# Generated deterministically by seda-macro-lef-normalizer-v1; recipe orfs-ng45-fakeram-metal3-coupledl2-pg-v1.
VERSION 5.8 ;
BUSBITCHARS "[]" ;
DIVIDERCHAR "/" ;

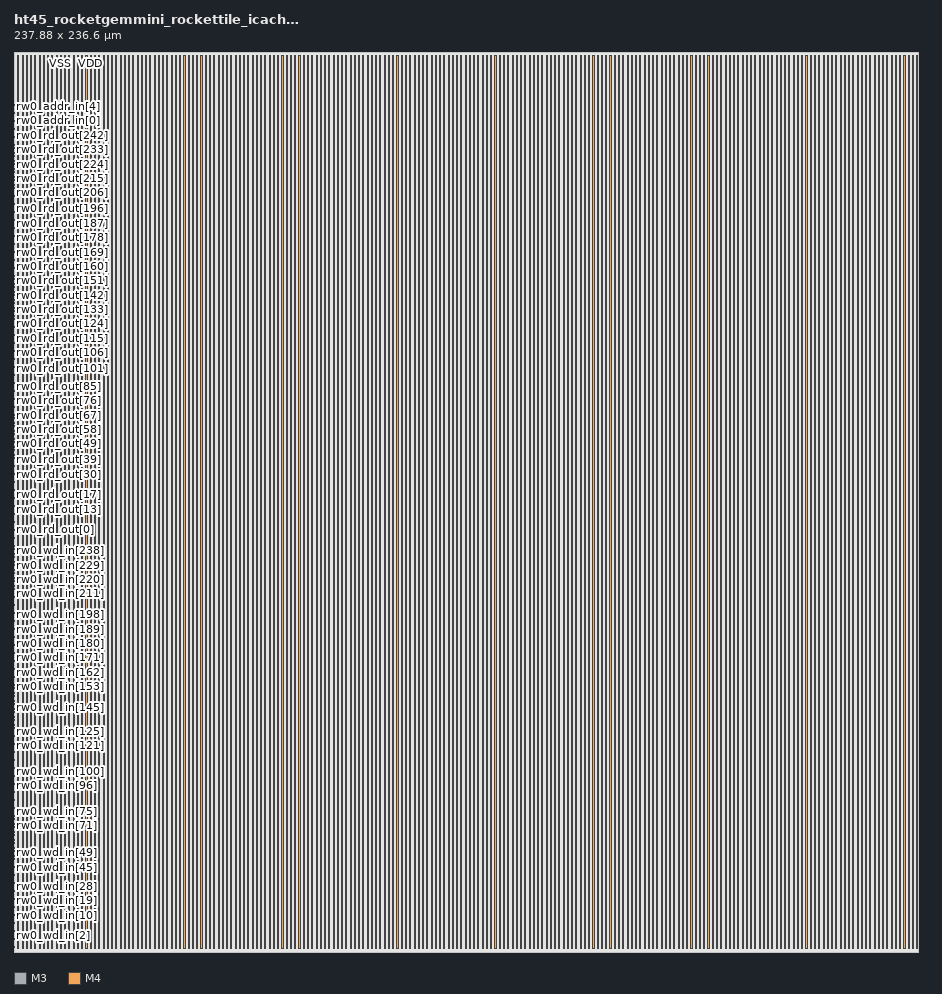
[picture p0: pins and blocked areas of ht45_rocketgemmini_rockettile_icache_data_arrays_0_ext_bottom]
MACRO ht45_rocketgemmini_rockettile_icache_data_arrays_0_ext_bottom
  FOREIGN ht45_rocketgemmini_rockettile_icache_data_arrays_0_ext_bottom 0 0 ;
  CLASS COVER ;
  ORIGIN 0 0 ;
  SIZE 237.88 BY 236.6 ;
  SYMMETRY X Y R90 ;
  PIN rw0_wmask_in[0]
    DIRECTION INPUT ;
    USE SIGNAL ;
    SHAPE ABUTMENT ;
    PORT
      LAYER M3 ;
      RECT 0 0.035 0.07 0.105 ;
    END
  END rw0_wmask_in[0]
  PIN rw0_wmask_in[1]
    DIRECTION INPUT ;
    USE SIGNAL ;
    SHAPE ABUTMENT ;
    PORT
      LAYER M3 ;
      RECT 0 0.455 0.07 0.525 ;
    END
  END rw0_wmask_in[1]
  PIN rw0_wmask_in[2]
    DIRECTION INPUT ;
    USE SIGNAL ;
    SHAPE ABUTMENT ;
    PORT
      LAYER M3 ;
      RECT 0 0.875 0.07 0.945 ;
    END
  END rw0_wmask_in[2]
  PIN rw0_wmask_in[3]
    DIRECTION INPUT ;
    USE SIGNAL ;
    SHAPE ABUTMENT ;
    PORT
      LAYER M3 ;
      RECT 0 1.295 0.07 1.365 ;
    END
  END rw0_wmask_in[3]
  PIN rw0_wmask_in[4]
    DIRECTION INPUT ;
    USE SIGNAL ;
    SHAPE ABUTMENT ;
    PORT
      LAYER M3 ;
      RECT 0 1.715 0.07 1.785 ;
    END
  END rw0_wmask_in[4]
  PIN rw0_wmask_in[5]
    DIRECTION INPUT ;
    USE SIGNAL ;
    SHAPE ABUTMENT ;
    PORT
      LAYER M3 ;
      RECT 0 2.135 0.07 2.205 ;
    END
  END rw0_wmask_in[5]
  PIN rw0_wmask_in[6]
    DIRECTION INPUT ;
    USE SIGNAL ;
    SHAPE ABUTMENT ;
    PORT
      LAYER M3 ;
      RECT 0 2.555 0.07 2.625 ;
    END
  END rw0_wmask_in[6]
  PIN rw0_wmask_in[7]
    DIRECTION INPUT ;
    USE SIGNAL ;
    SHAPE ABUTMENT ;
    PORT
      LAYER M3 ;
      RECT 0 2.975 0.07 3.045 ;
    END
  END rw0_wmask_in[7]
  PIN rw0_wd_in[0]
    DIRECTION INPUT ;
    USE SIGNAL ;
    SHAPE ABUTMENT ;
    PORT
      LAYER M3 ;
      RECT 0 3.395 0.07 3.465 ;
    END
  END rw0_wd_in[0]
  PIN rw0_wd_in[1]
    DIRECTION INPUT ;
    USE SIGNAL ;
    SHAPE ABUTMENT ;
    PORT
      LAYER M3 ;
      RECT 0 3.815 0.07 3.885 ;
    END
  END rw0_wd_in[1]
  PIN rw0_wd_in[2]
    DIRECTION INPUT ;
    USE SIGNAL ;
    SHAPE ABUTMENT ;
    PORT
      LAYER M3 ;
      RECT 0 4.235 0.07 4.305 ;
    END
  END rw0_wd_in[2]
  PIN rw0_wd_in[3]
    DIRECTION INPUT ;
    USE SIGNAL ;
    SHAPE ABUTMENT ;
    PORT
      LAYER M3 ;
      RECT 0 4.655 0.07 4.725 ;
    END
  END rw0_wd_in[3]
  PIN rw0_wd_in[4]
    DIRECTION INPUT ;
    USE SIGNAL ;
    SHAPE ABUTMENT ;
    PORT
      LAYER M3 ;
      RECT 0 5.075 0.07 5.145 ;
    END
  END rw0_wd_in[4]
  PIN rw0_wd_in[5]
    DIRECTION INPUT ;
    USE SIGNAL ;
    SHAPE ABUTMENT ;
    PORT
      LAYER M3 ;
      RECT 0 5.495 0.07 5.565 ;
    END
  END rw0_wd_in[5]
  PIN rw0_wd_in[6]
    DIRECTION INPUT ;
    USE SIGNAL ;
    SHAPE ABUTMENT ;
    PORT
      LAYER M3 ;
      RECT 0 5.915 0.07 5.985 ;
    END
  END rw0_wd_in[6]
  PIN rw0_wd_in[7]
    DIRECTION INPUT ;
    USE SIGNAL ;
    SHAPE ABUTMENT ;
    PORT
      LAYER M3 ;
      RECT 0 6.335 0.07 6.405 ;
    END
  END rw0_wd_in[7]
  PIN rw0_wd_in[8]
    DIRECTION INPUT ;
    USE SIGNAL ;
    SHAPE ABUTMENT ;
    PORT
      LAYER M3 ;
      RECT 0 6.755 0.07 6.825 ;
    END
  END rw0_wd_in[8]
  PIN rw0_wd_in[9]
    DIRECTION INPUT ;
    USE SIGNAL ;
    SHAPE ABUTMENT ;
    PORT
      LAYER M3 ;
      RECT 0 7.175 0.07 7.245 ;
    END
  END rw0_wd_in[9]
  PIN rw0_wd_in[10]
    DIRECTION INPUT ;
    USE SIGNAL ;
    SHAPE ABUTMENT ;
    PORT
      LAYER M3 ;
      RECT 0 7.595 0.07 7.665 ;
    END
  END rw0_wd_in[10]
  PIN rw0_wd_in[11]
    DIRECTION INPUT ;
    USE SIGNAL ;
    SHAPE ABUTMENT ;
    PORT
      LAYER M3 ;
      RECT 0 8.015 0.07 8.085 ;
    END
  END rw0_wd_in[11]
  PIN rw0_wd_in[12]
    DIRECTION INPUT ;
    USE SIGNAL ;
    SHAPE ABUTMENT ;
    PORT
      LAYER M3 ;
      RECT 0 8.435 0.07 8.505 ;
    END
  END rw0_wd_in[12]
  PIN rw0_wd_in[13]
    DIRECTION INPUT ;
    USE SIGNAL ;
    SHAPE ABUTMENT ;
    PORT
      LAYER M3 ;
      RECT 0 8.855 0.07 8.925 ;
    END
  END rw0_wd_in[13]
  PIN rw0_wd_in[14]
    DIRECTION INPUT ;
    USE SIGNAL ;
    SHAPE ABUTMENT ;
    PORT
      LAYER M3 ;
      RECT 0 9.275 0.07 9.345 ;
    END
  END rw0_wd_in[14]
  PIN rw0_wd_in[15]
    DIRECTION INPUT ;
    USE SIGNAL ;
    SHAPE ABUTMENT ;
    PORT
      LAYER M3 ;
      RECT 0 9.695 0.07 9.765 ;
    END
  END rw0_wd_in[15]
  PIN rw0_wd_in[16]
    DIRECTION INPUT ;
    USE SIGNAL ;
    SHAPE ABUTMENT ;
    PORT
      LAYER M3 ;
      RECT 0 10.115 0.07 10.185 ;
    END
  END rw0_wd_in[16]
  PIN rw0_wd_in[17]
    DIRECTION INPUT ;
    USE SIGNAL ;
    SHAPE ABUTMENT ;
    PORT
      LAYER M3 ;
      RECT 0 10.535 0.07 10.605 ;
    END
  END rw0_wd_in[17]
  PIN rw0_wd_in[18]
    DIRECTION INPUT ;
    USE SIGNAL ;
    SHAPE ABUTMENT ;
    PORT
      LAYER M3 ;
      RECT 0 10.955 0.07 11.025 ;
    END
  END rw0_wd_in[18]
  PIN rw0_wd_in[19]
    DIRECTION INPUT ;
    USE SIGNAL ;
    SHAPE ABUTMENT ;
    PORT
      LAYER M3 ;
      RECT 0 11.375 0.07 11.445 ;
    END
  END rw0_wd_in[19]
  PIN rw0_wd_in[20]
    DIRECTION INPUT ;
    USE SIGNAL ;
    SHAPE ABUTMENT ;
    PORT
      LAYER M3 ;
      RECT 0 11.795 0.07 11.865 ;
    END
  END rw0_wd_in[20]
  PIN rw0_wd_in[21]
    DIRECTION INPUT ;
    USE SIGNAL ;
    SHAPE ABUTMENT ;
    PORT
      LAYER M3 ;
      RECT 0 12.215 0.07 12.285 ;
    END
  END rw0_wd_in[21]
  PIN rw0_wd_in[22]
    DIRECTION INPUT ;
    USE SIGNAL ;
    SHAPE ABUTMENT ;
    PORT
      LAYER M3 ;
      RECT 0 12.635 0.07 12.705 ;
    END
  END rw0_wd_in[22]
  PIN rw0_wd_in[23]
    DIRECTION INPUT ;
    USE SIGNAL ;
    SHAPE ABUTMENT ;
    PORT
      LAYER M3 ;
      RECT 0 13.055 0.07 13.125 ;
    END
  END rw0_wd_in[23]
  PIN rw0_wd_in[24]
    DIRECTION INPUT ;
    USE SIGNAL ;
    SHAPE ABUTMENT ;
    PORT
      LAYER M3 ;
      RECT 0 13.475 0.07 13.545 ;
    END
  END rw0_wd_in[24]
  PIN rw0_wd_in[25]
    DIRECTION INPUT ;
    USE SIGNAL ;
    SHAPE ABUTMENT ;
    PORT
      LAYER M3 ;
      RECT 0 13.895 0.07 13.965 ;
    END
  END rw0_wd_in[25]
  PIN rw0_wd_in[26]
    DIRECTION INPUT ;
    USE SIGNAL ;
    SHAPE ABUTMENT ;
    PORT
      LAYER M3 ;
      RECT 0 14.315 0.07 14.385 ;
    END
  END rw0_wd_in[26]
  PIN rw0_wd_in[27]
    DIRECTION INPUT ;
    USE SIGNAL ;
    SHAPE ABUTMENT ;
    PORT
      LAYER M3 ;
      RECT 0 14.735 0.07 14.805 ;
    END
  END rw0_wd_in[27]
  PIN rw0_wd_in[28]
    DIRECTION INPUT ;
    USE SIGNAL ;
    SHAPE ABUTMENT ;
    PORT
      LAYER M3 ;
      RECT 0 15.155 0.07 15.225 ;
    END
  END rw0_wd_in[28]
  PIN rw0_wd_in[29]
    DIRECTION INPUT ;
    USE SIGNAL ;
    SHAPE ABUTMENT ;
    PORT
      LAYER M3 ;
      RECT 0 15.575 0.07 15.645 ;
    END
  END rw0_wd_in[29]
  PIN rw0_wd_in[30]
    DIRECTION INPUT ;
    USE SIGNAL ;
    SHAPE ABUTMENT ;
    PORT
      LAYER M3 ;
      RECT 0 15.995 0.07 16.065 ;
    END
  END rw0_wd_in[30]
  PIN rw0_wd_in[31]
    DIRECTION INPUT ;
    USE SIGNAL ;
    SHAPE ABUTMENT ;
    PORT
      LAYER M3 ;
      RECT 0 16.415 0.07 16.485 ;
    END
  END rw0_wd_in[31]
  PIN rw0_wd_in[32]
    DIRECTION INPUT ;
    USE SIGNAL ;
    SHAPE ABUTMENT ;
    PORT
      LAYER M3 ;
      RECT 0 16.835 0.07 16.905 ;
    END
  END rw0_wd_in[32]
  PIN rw0_wd_in[33]
    DIRECTION INPUT ;
    USE SIGNAL ;
    SHAPE ABUTMENT ;
    PORT
      LAYER M3 ;
      RECT 0 17.255 0.07 17.325 ;
    END
  END rw0_wd_in[33]
  PIN rw0_wd_in[34]
    DIRECTION INPUT ;
    USE SIGNAL ;
    SHAPE ABUTMENT ;
    PORT
      LAYER M3 ;
      RECT 0 17.675 0.07 17.745 ;
    END
  END rw0_wd_in[34]
  PIN rw0_wd_in[35]
    DIRECTION INPUT ;
    USE SIGNAL ;
    SHAPE ABUTMENT ;
    PORT
      LAYER M3 ;
      RECT 0 18.095 0.07 18.165 ;
    END
  END rw0_wd_in[35]
  PIN rw0_wd_in[36]
    DIRECTION INPUT ;
    USE SIGNAL ;
    SHAPE ABUTMENT ;
    PORT
      LAYER M3 ;
      RECT 0 18.515 0.07 18.585 ;
    END
  END rw0_wd_in[36]
  PIN rw0_wd_in[37]
    DIRECTION INPUT ;
    USE SIGNAL ;
    SHAPE ABUTMENT ;
    PORT
      LAYER M3 ;
      RECT 0 18.935 0.07 19.005 ;
    END
  END rw0_wd_in[37]
  PIN rw0_wd_in[38]
    DIRECTION INPUT ;
    USE SIGNAL ;
    SHAPE ABUTMENT ;
    PORT
      LAYER M3 ;
      RECT 0 19.355 0.07 19.425 ;
    END
  END rw0_wd_in[38]
  PIN rw0_wd_in[39]
    DIRECTION INPUT ;
    USE SIGNAL ;
    SHAPE ABUTMENT ;
    PORT
      LAYER M3 ;
      RECT 0 19.775 0.07 19.845 ;
    END
  END rw0_wd_in[39]
  PIN rw0_wd_in[40]
    DIRECTION INPUT ;
    USE SIGNAL ;
    SHAPE ABUTMENT ;
    PORT
      LAYER M3 ;
      RECT 0 20.195 0.07 20.265 ;
    END
  END rw0_wd_in[40]
  PIN rw0_wd_in[41]
    DIRECTION INPUT ;
    USE SIGNAL ;
    SHAPE ABUTMENT ;
    PORT
      LAYER M3 ;
      RECT 0 20.615 0.07 20.685 ;
    END
  END rw0_wd_in[41]
  PIN rw0_wd_in[42]
    DIRECTION INPUT ;
    USE SIGNAL ;
    SHAPE ABUTMENT ;
    PORT
      LAYER M3 ;
      RECT 0 21.035 0.07 21.105 ;
    END
  END rw0_wd_in[42]
  PIN rw0_wd_in[43]
    DIRECTION INPUT ;
    USE SIGNAL ;
    SHAPE ABUTMENT ;
    PORT
      LAYER M3 ;
      RECT 0 21.455 0.07 21.525 ;
    END
  END rw0_wd_in[43]
  PIN rw0_wd_in[44]
    DIRECTION INPUT ;
    USE SIGNAL ;
    SHAPE ABUTMENT ;
    PORT
      LAYER M3 ;
      RECT 0 21.875 0.07 21.945 ;
    END
  END rw0_wd_in[44]
  PIN rw0_wd_in[45]
    DIRECTION INPUT ;
    USE SIGNAL ;
    SHAPE ABUTMENT ;
    PORT
      LAYER M3 ;
      RECT 0 22.295 0.07 22.365 ;
    END
  END rw0_wd_in[45]
  PIN rw0_wd_in[46]
    DIRECTION INPUT ;
    USE SIGNAL ;
    SHAPE ABUTMENT ;
    PORT
      LAYER M3 ;
      RECT 0 22.715 0.07 22.785 ;
    END
  END rw0_wd_in[46]
  PIN rw0_wd_in[47]
    DIRECTION INPUT ;
    USE SIGNAL ;
    SHAPE ABUTMENT ;
    PORT
      LAYER M3 ;
      RECT 0 23.135 0.07 23.205 ;
    END
  END rw0_wd_in[47]
  PIN rw0_wd_in[48]
    DIRECTION INPUT ;
    USE SIGNAL ;
    SHAPE ABUTMENT ;
    PORT
      LAYER M3 ;
      RECT 0 23.555 0.07 23.625 ;
    END
  END rw0_wd_in[48]
  PIN rw0_wd_in[49]
    DIRECTION INPUT ;
    USE SIGNAL ;
    SHAPE ABUTMENT ;
    PORT
      LAYER M3 ;
      RECT 0 23.975 0.07 24.045 ;
    END
  END rw0_wd_in[49]
  PIN rw0_wd_in[50]
    DIRECTION INPUT ;
    USE SIGNAL ;
    SHAPE ABUTMENT ;
    PORT
      LAYER M3 ;
      RECT 0 24.395 0.07 24.465 ;
    END
  END rw0_wd_in[50]
  PIN rw0_wd_in[51]
    DIRECTION INPUT ;
    USE SIGNAL ;
    SHAPE ABUTMENT ;
    PORT
      LAYER M3 ;
      RECT 0 24.815 0.07 24.885 ;
    END
  END rw0_wd_in[51]
  PIN rw0_wd_in[52]
    DIRECTION INPUT ;
    USE SIGNAL ;
    SHAPE ABUTMENT ;
    PORT
      LAYER M3 ;
      RECT 0 25.235 0.07 25.305 ;
    END
  END rw0_wd_in[52]
  PIN rw0_wd_in[53]
    DIRECTION INPUT ;
    USE SIGNAL ;
    SHAPE ABUTMENT ;
    PORT
      LAYER M3 ;
      RECT 0 25.655 0.07 25.725 ;
    END
  END rw0_wd_in[53]
  PIN rw0_wd_in[54]
    DIRECTION INPUT ;
    USE SIGNAL ;
    SHAPE ABUTMENT ;
    PORT
      LAYER M3 ;
      RECT 0 26.075 0.07 26.145 ;
    END
  END rw0_wd_in[54]
  PIN rw0_wd_in[55]
    DIRECTION INPUT ;
    USE SIGNAL ;
    SHAPE ABUTMENT ;
    PORT
      LAYER M3 ;
      RECT 0 26.495 0.07 26.565 ;
    END
  END rw0_wd_in[55]
  PIN rw0_wd_in[56]
    DIRECTION INPUT ;
    USE SIGNAL ;
    SHAPE ABUTMENT ;
    PORT
      LAYER M3 ;
      RECT 0 26.915 0.07 26.985 ;
    END
  END rw0_wd_in[56]
  PIN rw0_wd_in[57]
    DIRECTION INPUT ;
    USE SIGNAL ;
    SHAPE ABUTMENT ;
    PORT
      LAYER M3 ;
      RECT 0 27.335 0.07 27.405 ;
    END
  END rw0_wd_in[57]
  PIN rw0_wd_in[58]
    DIRECTION INPUT ;
    USE SIGNAL ;
    SHAPE ABUTMENT ;
    PORT
      LAYER M3 ;
      RECT 0 27.755 0.07 27.825 ;
    END
  END rw0_wd_in[58]
  PIN rw0_wd_in[59]
    DIRECTION INPUT ;
    USE SIGNAL ;
    SHAPE ABUTMENT ;
    PORT
      LAYER M3 ;
      RECT 0 28.175 0.07 28.245 ;
    END
  END rw0_wd_in[59]
  PIN rw0_wd_in[60]
    DIRECTION INPUT ;
    USE SIGNAL ;
    SHAPE ABUTMENT ;
    PORT
      LAYER M3 ;
      RECT 0 28.595 0.07 28.665 ;
    END
  END rw0_wd_in[60]
  PIN rw0_wd_in[61]
    DIRECTION INPUT ;
    USE SIGNAL ;
    SHAPE ABUTMENT ;
    PORT
      LAYER M3 ;
      RECT 0 29.015 0.07 29.085 ;
    END
  END rw0_wd_in[61]
  PIN rw0_wd_in[62]
    DIRECTION INPUT ;
    USE SIGNAL ;
    SHAPE ABUTMENT ;
    PORT
      LAYER M3 ;
      RECT 0 29.435 0.07 29.505 ;
    END
  END rw0_wd_in[62]
  PIN rw0_wd_in[63]
    DIRECTION INPUT ;
    USE SIGNAL ;
    SHAPE ABUTMENT ;
    PORT
      LAYER M3 ;
      RECT 0 29.855 0.07 29.925 ;
    END
  END rw0_wd_in[63]
  PIN rw0_wd_in[64]
    DIRECTION INPUT ;
    USE SIGNAL ;
    SHAPE ABUTMENT ;
    PORT
      LAYER M3 ;
      RECT 0 30.275 0.07 30.345 ;
    END
  END rw0_wd_in[64]
  PIN rw0_wd_in[65]
    DIRECTION INPUT ;
    USE SIGNAL ;
    SHAPE ABUTMENT ;
    PORT
      LAYER M3 ;
      RECT 0 30.695 0.07 30.765 ;
    END
  END rw0_wd_in[65]
  PIN rw0_wd_in[66]
    DIRECTION INPUT ;
    USE SIGNAL ;
    SHAPE ABUTMENT ;
    PORT
      LAYER M3 ;
      RECT 0 31.115 0.07 31.185 ;
    END
  END rw0_wd_in[66]
  PIN rw0_wd_in[67]
    DIRECTION INPUT ;
    USE SIGNAL ;
    SHAPE ABUTMENT ;
    PORT
      LAYER M3 ;
      RECT 0 31.535 0.07 31.605 ;
    END
  END rw0_wd_in[67]
  PIN rw0_wd_in[68]
    DIRECTION INPUT ;
    USE SIGNAL ;
    SHAPE ABUTMENT ;
    PORT
      LAYER M3 ;
      RECT 0 31.955 0.07 32.025 ;
    END
  END rw0_wd_in[68]
  PIN rw0_wd_in[69]
    DIRECTION INPUT ;
    USE SIGNAL ;
    SHAPE ABUTMENT ;
    PORT
      LAYER M3 ;
      RECT 0 32.375 0.07 32.445 ;
    END
  END rw0_wd_in[69]
  PIN rw0_wd_in[70]
    DIRECTION INPUT ;
    USE SIGNAL ;
    SHAPE ABUTMENT ;
    PORT
      LAYER M3 ;
      RECT 0 32.795 0.07 32.865 ;
    END
  END rw0_wd_in[70]
  PIN rw0_wd_in[71]
    DIRECTION INPUT ;
    USE SIGNAL ;
    SHAPE ABUTMENT ;
    PORT
      LAYER M3 ;
      RECT 0 33.215 0.07 33.285 ;
    END
  END rw0_wd_in[71]
  PIN rw0_wd_in[72]
    DIRECTION INPUT ;
    USE SIGNAL ;
    SHAPE ABUTMENT ;
    PORT
      LAYER M3 ;
      RECT 0 33.635 0.07 33.705 ;
    END
  END rw0_wd_in[72]
  PIN rw0_wd_in[73]
    DIRECTION INPUT ;
    USE SIGNAL ;
    SHAPE ABUTMENT ;
    PORT
      LAYER M3 ;
      RECT 0 34.055 0.07 34.125 ;
    END
  END rw0_wd_in[73]
  PIN rw0_wd_in[74]
    DIRECTION INPUT ;
    USE SIGNAL ;
    SHAPE ABUTMENT ;
    PORT
      LAYER M3 ;
      RECT 0 34.475 0.07 34.545 ;
    END
  END rw0_wd_in[74]
  PIN rw0_wd_in[75]
    DIRECTION INPUT ;
    USE SIGNAL ;
    SHAPE ABUTMENT ;
    PORT
      LAYER M3 ;
      RECT 0 34.895 0.07 34.965 ;
    END
  END rw0_wd_in[75]
  PIN rw0_wd_in[76]
    DIRECTION INPUT ;
    USE SIGNAL ;
    SHAPE ABUTMENT ;
    PORT
      LAYER M3 ;
      RECT 0 35.315 0.07 35.385 ;
    END
  END rw0_wd_in[76]
  PIN rw0_wd_in[77]
    DIRECTION INPUT ;
    USE SIGNAL ;
    SHAPE ABUTMENT ;
    PORT
      LAYER M3 ;
      RECT 0 35.735 0.07 35.805 ;
    END
  END rw0_wd_in[77]
  PIN rw0_wd_in[78]
    DIRECTION INPUT ;
    USE SIGNAL ;
    SHAPE ABUTMENT ;
    PORT
      LAYER M3 ;
      RECT 0 36.155 0.07 36.225 ;
    END
  END rw0_wd_in[78]
  PIN rw0_wd_in[79]
    DIRECTION INPUT ;
    USE SIGNAL ;
    SHAPE ABUTMENT ;
    PORT
      LAYER M3 ;
      RECT 0 36.575 0.07 36.645 ;
    END
  END rw0_wd_in[79]
  PIN rw0_wd_in[80]
    DIRECTION INPUT ;
    USE SIGNAL ;
    SHAPE ABUTMENT ;
    PORT
      LAYER M3 ;
      RECT 0 36.995 0.07 37.065 ;
    END
  END rw0_wd_in[80]
  PIN rw0_wd_in[81]
    DIRECTION INPUT ;
    USE SIGNAL ;
    SHAPE ABUTMENT ;
    PORT
      LAYER M3 ;
      RECT 0 37.415 0.07 37.485 ;
    END
  END rw0_wd_in[81]
  PIN rw0_wd_in[82]
    DIRECTION INPUT ;
    USE SIGNAL ;
    SHAPE ABUTMENT ;
    PORT
      LAYER M3 ;
      RECT 0 37.835 0.07 37.905 ;
    END
  END rw0_wd_in[82]
  PIN rw0_wd_in[83]
    DIRECTION INPUT ;
    USE SIGNAL ;
    SHAPE ABUTMENT ;
    PORT
      LAYER M3 ;
      RECT 0 38.255 0.07 38.325 ;
    END
  END rw0_wd_in[83]
  PIN rw0_wd_in[84]
    DIRECTION INPUT ;
    USE SIGNAL ;
    SHAPE ABUTMENT ;
    PORT
      LAYER M3 ;
      RECT 0 38.675 0.07 38.745 ;
    END
  END rw0_wd_in[84]
  PIN rw0_wd_in[85]
    DIRECTION INPUT ;
    USE SIGNAL ;
    SHAPE ABUTMENT ;
    PORT
      LAYER M3 ;
      RECT 0 39.095 0.07 39.165 ;
    END
  END rw0_wd_in[85]
  PIN rw0_wd_in[86]
    DIRECTION INPUT ;
    USE SIGNAL ;
    SHAPE ABUTMENT ;
    PORT
      LAYER M3 ;
      RECT 0 39.515 0.07 39.585 ;
    END
  END rw0_wd_in[86]
  PIN rw0_wd_in[87]
    DIRECTION INPUT ;
    USE SIGNAL ;
    SHAPE ABUTMENT ;
    PORT
      LAYER M3 ;
      RECT 0 39.935 0.07 40.005 ;
    END
  END rw0_wd_in[87]
  PIN rw0_wd_in[88]
    DIRECTION INPUT ;
    USE SIGNAL ;
    SHAPE ABUTMENT ;
    PORT
      LAYER M3 ;
      RECT 0 40.355 0.07 40.425 ;
    END
  END rw0_wd_in[88]
  PIN rw0_wd_in[89]
    DIRECTION INPUT ;
    USE SIGNAL ;
    SHAPE ABUTMENT ;
    PORT
      LAYER M3 ;
      RECT 0 40.775 0.07 40.845 ;
    END
  END rw0_wd_in[89]
  PIN rw0_wd_in[90]
    DIRECTION INPUT ;
    USE SIGNAL ;
    SHAPE ABUTMENT ;
    PORT
      LAYER M3 ;
      RECT 0 41.195 0.07 41.265 ;
    END
  END rw0_wd_in[90]
  PIN rw0_wd_in[91]
    DIRECTION INPUT ;
    USE SIGNAL ;
    SHAPE ABUTMENT ;
    PORT
      LAYER M3 ;
      RECT 0 41.615 0.07 41.685 ;
    END
  END rw0_wd_in[91]
  PIN rw0_wd_in[92]
    DIRECTION INPUT ;
    USE SIGNAL ;
    SHAPE ABUTMENT ;
    PORT
      LAYER M3 ;
      RECT 0 42.035 0.07 42.105 ;
    END
  END rw0_wd_in[92]
  PIN rw0_wd_in[93]
    DIRECTION INPUT ;
    USE SIGNAL ;
    SHAPE ABUTMENT ;
    PORT
      LAYER M3 ;
      RECT 0 42.455 0.07 42.525 ;
    END
  END rw0_wd_in[93]
  PIN rw0_wd_in[94]
    DIRECTION INPUT ;
    USE SIGNAL ;
    SHAPE ABUTMENT ;
    PORT
      LAYER M3 ;
      RECT 0 42.875 0.07 42.945 ;
    END
  END rw0_wd_in[94]
  PIN rw0_wd_in[95]
    DIRECTION INPUT ;
    USE SIGNAL ;
    SHAPE ABUTMENT ;
    PORT
      LAYER M3 ;
      RECT 0 43.295 0.07 43.365 ;
    END
  END rw0_wd_in[95]
  PIN rw0_wd_in[96]
    DIRECTION INPUT ;
    USE SIGNAL ;
    SHAPE ABUTMENT ;
    PORT
      LAYER M3 ;
      RECT 0 43.715 0.07 43.785 ;
    END
  END rw0_wd_in[96]
  PIN rw0_wd_in[97]
    DIRECTION INPUT ;
    USE SIGNAL ;
    SHAPE ABUTMENT ;
    PORT
      LAYER M3 ;
      RECT 0 44.135 0.07 44.205 ;
    END
  END rw0_wd_in[97]
  PIN rw0_wd_in[98]
    DIRECTION INPUT ;
    USE SIGNAL ;
    SHAPE ABUTMENT ;
    PORT
      LAYER M3 ;
      RECT 0 44.555 0.07 44.625 ;
    END
  END rw0_wd_in[98]
  PIN rw0_wd_in[99]
    DIRECTION INPUT ;
    USE SIGNAL ;
    SHAPE ABUTMENT ;
    PORT
      LAYER M3 ;
      RECT 0 44.975 0.07 45.045 ;
    END
  END rw0_wd_in[99]
  PIN rw0_wd_in[100]
    DIRECTION INPUT ;
    USE SIGNAL ;
    SHAPE ABUTMENT ;
    PORT
      LAYER M3 ;
      RECT 0 45.395 0.07 45.465 ;
    END
  END rw0_wd_in[100]
  PIN rw0_wd_in[101]
    DIRECTION INPUT ;
    USE SIGNAL ;
    SHAPE ABUTMENT ;
    PORT
      LAYER M3 ;
      RECT 0 45.815 0.07 45.885 ;
    END
  END rw0_wd_in[101]
  PIN rw0_wd_in[102]
    DIRECTION INPUT ;
    USE SIGNAL ;
    SHAPE ABUTMENT ;
    PORT
      LAYER M3 ;
      RECT 0 46.235 0.07 46.305 ;
    END
  END rw0_wd_in[102]
  PIN rw0_wd_in[103]
    DIRECTION INPUT ;
    USE SIGNAL ;
    SHAPE ABUTMENT ;
    PORT
      LAYER M3 ;
      RECT 0 46.655 0.07 46.725 ;
    END
  END rw0_wd_in[103]
  PIN rw0_wd_in[104]
    DIRECTION INPUT ;
    USE SIGNAL ;
    SHAPE ABUTMENT ;
    PORT
      LAYER M3 ;
      RECT 0 47.075 0.07 47.145 ;
    END
  END rw0_wd_in[104]
  PIN rw0_wd_in[105]
    DIRECTION INPUT ;
    USE SIGNAL ;
    SHAPE ABUTMENT ;
    PORT
      LAYER M3 ;
      RECT 0 47.495 0.07 47.565 ;
    END
  END rw0_wd_in[105]
  PIN rw0_wd_in[106]
    DIRECTION INPUT ;
    USE SIGNAL ;
    SHAPE ABUTMENT ;
    PORT
      LAYER M3 ;
      RECT 0 47.915 0.07 47.985 ;
    END
  END rw0_wd_in[106]
  PIN rw0_wd_in[107]
    DIRECTION INPUT ;
    USE SIGNAL ;
    SHAPE ABUTMENT ;
    PORT
      LAYER M3 ;
      RECT 0 48.335 0.07 48.405 ;
    END
  END rw0_wd_in[107]
  PIN rw0_wd_in[108]
    DIRECTION INPUT ;
    USE SIGNAL ;
    SHAPE ABUTMENT ;
    PORT
      LAYER M3 ;
      RECT 0 48.755 0.07 48.825 ;
    END
  END rw0_wd_in[108]
  PIN rw0_wd_in[109]
    DIRECTION INPUT ;
    USE SIGNAL ;
    SHAPE ABUTMENT ;
    PORT
      LAYER M3 ;
      RECT 0 49.175 0.07 49.245 ;
    END
  END rw0_wd_in[109]
  PIN rw0_wd_in[110]
    DIRECTION INPUT ;
    USE SIGNAL ;
    SHAPE ABUTMENT ;
    PORT
      LAYER M3 ;
      RECT 0 49.595 0.07 49.665 ;
    END
  END rw0_wd_in[110]
  PIN rw0_wd_in[111]
    DIRECTION INPUT ;
    USE SIGNAL ;
    SHAPE ABUTMENT ;
    PORT
      LAYER M3 ;
      RECT 0 50.015 0.07 50.085 ;
    END
  END rw0_wd_in[111]
  PIN rw0_wd_in[112]
    DIRECTION INPUT ;
    USE SIGNAL ;
    SHAPE ABUTMENT ;
    PORT
      LAYER M3 ;
      RECT 0 50.435 0.07 50.505 ;
    END
  END rw0_wd_in[112]
  PIN rw0_wd_in[113]
    DIRECTION INPUT ;
    USE SIGNAL ;
    SHAPE ABUTMENT ;
    PORT
      LAYER M3 ;
      RECT 0 50.855 0.07 50.925 ;
    END
  END rw0_wd_in[113]
  PIN rw0_wd_in[114]
    DIRECTION INPUT ;
    USE SIGNAL ;
    SHAPE ABUTMENT ;
    PORT
      LAYER M3 ;
      RECT 0 51.275 0.07 51.345 ;
    END
  END rw0_wd_in[114]
  PIN rw0_wd_in[115]
    DIRECTION INPUT ;
    USE SIGNAL ;
    SHAPE ABUTMENT ;
    PORT
      LAYER M3 ;
      RECT 0 51.695 0.07 51.765 ;
    END
  END rw0_wd_in[115]
  PIN rw0_wd_in[116]
    DIRECTION INPUT ;
    USE SIGNAL ;
    SHAPE ABUTMENT ;
    PORT
      LAYER M3 ;
      RECT 0 52.115 0.07 52.185 ;
    END
  END rw0_wd_in[116]
  PIN rw0_wd_in[117]
    DIRECTION INPUT ;
    USE SIGNAL ;
    SHAPE ABUTMENT ;
    PORT
      LAYER M3 ;
      RECT 0 52.535 0.07 52.605 ;
    END
  END rw0_wd_in[117]
  PIN rw0_wd_in[118]
    DIRECTION INPUT ;
    USE SIGNAL ;
    SHAPE ABUTMENT ;
    PORT
      LAYER M3 ;
      RECT 0 52.955 0.07 53.025 ;
    END
  END rw0_wd_in[118]
  PIN rw0_wd_in[119]
    DIRECTION INPUT ;
    USE SIGNAL ;
    SHAPE ABUTMENT ;
    PORT
      LAYER M3 ;
      RECT 0 53.375 0.07 53.445 ;
    END
  END rw0_wd_in[119]
  PIN rw0_wd_in[120]
    DIRECTION INPUT ;
    USE SIGNAL ;
    SHAPE ABUTMENT ;
    PORT
      LAYER M3 ;
      RECT 0 53.795 0.07 53.865 ;
    END
  END rw0_wd_in[120]
  PIN rw0_wd_in[121]
    DIRECTION INPUT ;
    USE SIGNAL ;
    SHAPE ABUTMENT ;
    PORT
      LAYER M3 ;
      RECT 0 54.215 0.07 54.285 ;
    END
  END rw0_wd_in[121]
  PIN rw0_wd_in[122]
    DIRECTION INPUT ;
    USE SIGNAL ;
    SHAPE ABUTMENT ;
    PORT
      LAYER M3 ;
      RECT 0 54.635 0.07 54.705 ;
    END
  END rw0_wd_in[122]
  PIN rw0_wd_in[123]
    DIRECTION INPUT ;
    USE SIGNAL ;
    SHAPE ABUTMENT ;
    PORT
      LAYER M3 ;
      RECT 0 55.055 0.07 55.125 ;
    END
  END rw0_wd_in[123]
  PIN rw0_wd_in[124]
    DIRECTION INPUT ;
    USE SIGNAL ;
    SHAPE ABUTMENT ;
    PORT
      LAYER M3 ;
      RECT 0 55.475 0.07 55.545 ;
    END
  END rw0_wd_in[124]
  PIN rw0_wd_in[125]
    DIRECTION INPUT ;
    USE SIGNAL ;
    SHAPE ABUTMENT ;
    PORT
      LAYER M3 ;
      RECT 0 55.895 0.07 55.965 ;
    END
  END rw0_wd_in[125]
  PIN rw0_wd_in[126]
    DIRECTION INPUT ;
    USE SIGNAL ;
    SHAPE ABUTMENT ;
    PORT
      LAYER M3 ;
      RECT 0 56.315 0.07 56.385 ;
    END
  END rw0_wd_in[126]
  PIN rw0_wd_in[127]
    DIRECTION INPUT ;
    USE SIGNAL ;
    SHAPE ABUTMENT ;
    PORT
      LAYER M3 ;
      RECT 0 56.735 0.07 56.805 ;
    END
  END rw0_wd_in[127]
  PIN rw0_wd_in[128]
    DIRECTION INPUT ;
    USE SIGNAL ;
    SHAPE ABUTMENT ;
    PORT
      LAYER M3 ;
      RECT 0 57.155 0.07 57.225 ;
    END
  END rw0_wd_in[128]
  PIN rw0_wd_in[129]
    DIRECTION INPUT ;
    USE SIGNAL ;
    SHAPE ABUTMENT ;
    PORT
      LAYER M3 ;
      RECT 0 57.575 0.07 57.645 ;
    END
  END rw0_wd_in[129]
  PIN rw0_wd_in[130]
    DIRECTION INPUT ;
    USE SIGNAL ;
    SHAPE ABUTMENT ;
    PORT
      LAYER M3 ;
      RECT 0 57.995 0.07 58.065 ;
    END
  END rw0_wd_in[130]
  PIN rw0_wd_in[131]
    DIRECTION INPUT ;
    USE SIGNAL ;
    SHAPE ABUTMENT ;
    PORT
      LAYER M3 ;
      RECT 0 58.415 0.07 58.485 ;
    END
  END rw0_wd_in[131]
  PIN rw0_wd_in[132]
    DIRECTION INPUT ;
    USE SIGNAL ;
    SHAPE ABUTMENT ;
    PORT
      LAYER M3 ;
      RECT 0 58.835 0.07 58.905 ;
    END
  END rw0_wd_in[132]
  PIN rw0_wd_in[133]
    DIRECTION INPUT ;
    USE SIGNAL ;
    SHAPE ABUTMENT ;
    PORT
      LAYER M3 ;
      RECT 0 59.255 0.07 59.325 ;
    END
  END rw0_wd_in[133]
  PIN rw0_wd_in[134]
    DIRECTION INPUT ;
    USE SIGNAL ;
    SHAPE ABUTMENT ;
    PORT
      LAYER M3 ;
      RECT 0 59.675 0.07 59.745 ;
    END
  END rw0_wd_in[134]
  PIN rw0_wd_in[135]
    DIRECTION INPUT ;
    USE SIGNAL ;
    SHAPE ABUTMENT ;
    PORT
      LAYER M3 ;
      RECT 0 60.095 0.07 60.165 ;
    END
  END rw0_wd_in[135]
  PIN rw0_wd_in[136]
    DIRECTION INPUT ;
    USE SIGNAL ;
    SHAPE ABUTMENT ;
    PORT
      LAYER M3 ;
      RECT 0 60.515 0.07 60.585 ;
    END
  END rw0_wd_in[136]
  PIN rw0_wd_in[137]
    DIRECTION INPUT ;
    USE SIGNAL ;
    SHAPE ABUTMENT ;
    PORT
      LAYER M3 ;
      RECT 0 60.935 0.07 61.005 ;
    END
  END rw0_wd_in[137]
  PIN rw0_wd_in[138]
    DIRECTION INPUT ;
    USE SIGNAL ;
    SHAPE ABUTMENT ;
    PORT
      LAYER M3 ;
      RECT 0 61.355 0.07 61.425 ;
    END
  END rw0_wd_in[138]
  PIN rw0_wd_in[139]
    DIRECTION INPUT ;
    USE SIGNAL ;
    SHAPE ABUTMENT ;
    PORT
      LAYER M3 ;
      RECT 0 61.775 0.07 61.845 ;
    END
  END rw0_wd_in[139]
  PIN rw0_wd_in[140]
    DIRECTION INPUT ;
    USE SIGNAL ;
    SHAPE ABUTMENT ;
    PORT
      LAYER M3 ;
      RECT 0 62.195 0.07 62.265 ;
    END
  END rw0_wd_in[140]
  PIN rw0_wd_in[141]
    DIRECTION INPUT ;
    USE SIGNAL ;
    SHAPE ABUTMENT ;
    PORT
      LAYER M3 ;
      RECT 0 62.615 0.07 62.685 ;
    END
  END rw0_wd_in[141]
  PIN rw0_wd_in[142]
    DIRECTION INPUT ;
    USE SIGNAL ;
    SHAPE ABUTMENT ;
    PORT
      LAYER M3 ;
      RECT 0 63.035 0.07 63.105 ;
    END
  END rw0_wd_in[142]
  PIN rw0_wd_in[143]
    DIRECTION INPUT ;
    USE SIGNAL ;
    SHAPE ABUTMENT ;
    PORT
      LAYER M3 ;
      RECT 0 63.455 0.07 63.525 ;
    END
  END rw0_wd_in[143]
  PIN rw0_wd_in[144]
    DIRECTION INPUT ;
    USE SIGNAL ;
    SHAPE ABUTMENT ;
    PORT
      LAYER M3 ;
      RECT 0 63.875 0.07 63.945 ;
    END
  END rw0_wd_in[144]
  PIN rw0_wd_in[145]
    DIRECTION INPUT ;
    USE SIGNAL ;
    SHAPE ABUTMENT ;
    PORT
      LAYER M3 ;
      RECT 0 64.295 0.07 64.365 ;
    END
  END rw0_wd_in[145]
  PIN rw0_wd_in[146]
    DIRECTION INPUT ;
    USE SIGNAL ;
    SHAPE ABUTMENT ;
    PORT
      LAYER M3 ;
      RECT 0 64.715 0.07 64.785 ;
    END
  END rw0_wd_in[146]
  PIN rw0_wd_in[147]
    DIRECTION INPUT ;
    USE SIGNAL ;
    SHAPE ABUTMENT ;
    PORT
      LAYER M3 ;
      RECT 0 65.135 0.07 65.205 ;
    END
  END rw0_wd_in[147]
  PIN rw0_wd_in[148]
    DIRECTION INPUT ;
    USE SIGNAL ;
    SHAPE ABUTMENT ;
    PORT
      LAYER M3 ;
      RECT 0 65.555 0.07 65.625 ;
    END
  END rw0_wd_in[148]
  PIN rw0_wd_in[149]
    DIRECTION INPUT ;
    USE SIGNAL ;
    SHAPE ABUTMENT ;
    PORT
      LAYER M3 ;
      RECT 0 65.975 0.07 66.045 ;
    END
  END rw0_wd_in[149]
  PIN rw0_wd_in[150]
    DIRECTION INPUT ;
    USE SIGNAL ;
    SHAPE ABUTMENT ;
    PORT
      LAYER M3 ;
      RECT 0 66.395 0.07 66.465 ;
    END
  END rw0_wd_in[150]
  PIN rw0_wd_in[151]
    DIRECTION INPUT ;
    USE SIGNAL ;
    SHAPE ABUTMENT ;
    PORT
      LAYER M3 ;
      RECT 0 66.815 0.07 66.885 ;
    END
  END rw0_wd_in[151]
  PIN rw0_wd_in[152]
    DIRECTION INPUT ;
    USE SIGNAL ;
    SHAPE ABUTMENT ;
    PORT
      LAYER M3 ;
      RECT 0 67.235 0.07 67.305 ;
    END
  END rw0_wd_in[152]
  PIN rw0_wd_in[153]
    DIRECTION INPUT ;
    USE SIGNAL ;
    SHAPE ABUTMENT ;
    PORT
      LAYER M3 ;
      RECT 0 67.655 0.07 67.725 ;
    END
  END rw0_wd_in[153]
  PIN rw0_wd_in[154]
    DIRECTION INPUT ;
    USE SIGNAL ;
    SHAPE ABUTMENT ;
    PORT
      LAYER M3 ;
      RECT 0 68.075 0.07 68.145 ;
    END
  END rw0_wd_in[154]
  PIN rw0_wd_in[155]
    DIRECTION INPUT ;
    USE SIGNAL ;
    SHAPE ABUTMENT ;
    PORT
      LAYER M3 ;
      RECT 0 68.495 0.07 68.565 ;
    END
  END rw0_wd_in[155]
  PIN rw0_wd_in[156]
    DIRECTION INPUT ;
    USE SIGNAL ;
    SHAPE ABUTMENT ;
    PORT
      LAYER M3 ;
      RECT 0 68.915 0.07 68.985 ;
    END
  END rw0_wd_in[156]
  PIN rw0_wd_in[157]
    DIRECTION INPUT ;
    USE SIGNAL ;
    SHAPE ABUTMENT ;
    PORT
      LAYER M3 ;
      RECT 0 69.335 0.07 69.405 ;
    END
  END rw0_wd_in[157]
  PIN rw0_wd_in[158]
    DIRECTION INPUT ;
    USE SIGNAL ;
    SHAPE ABUTMENT ;
    PORT
      LAYER M3 ;
      RECT 0 69.755 0.07 69.825 ;
    END
  END rw0_wd_in[158]
  PIN rw0_wd_in[159]
    DIRECTION INPUT ;
    USE SIGNAL ;
    SHAPE ABUTMENT ;
    PORT
      LAYER M3 ;
      RECT 0 70.175 0.07 70.245 ;
    END
  END rw0_wd_in[159]
  PIN rw0_wd_in[160]
    DIRECTION INPUT ;
    USE SIGNAL ;
    SHAPE ABUTMENT ;
    PORT
      LAYER M3 ;
      RECT 0 70.595 0.07 70.665 ;
    END
  END rw0_wd_in[160]
  PIN rw0_wd_in[161]
    DIRECTION INPUT ;
    USE SIGNAL ;
    SHAPE ABUTMENT ;
    PORT
      LAYER M3 ;
      RECT 0 71.015 0.07 71.085 ;
    END
  END rw0_wd_in[161]
  PIN rw0_wd_in[162]
    DIRECTION INPUT ;
    USE SIGNAL ;
    SHAPE ABUTMENT ;
    PORT
      LAYER M3 ;
      RECT 0 71.435 0.07 71.505 ;
    END
  END rw0_wd_in[162]
  PIN rw0_wd_in[163]
    DIRECTION INPUT ;
    USE SIGNAL ;
    SHAPE ABUTMENT ;
    PORT
      LAYER M3 ;
      RECT 0 71.855 0.07 71.925 ;
    END
  END rw0_wd_in[163]
  PIN rw0_wd_in[164]
    DIRECTION INPUT ;
    USE SIGNAL ;
    SHAPE ABUTMENT ;
    PORT
      LAYER M3 ;
      RECT 0 72.275 0.07 72.345 ;
    END
  END rw0_wd_in[164]
  PIN rw0_wd_in[165]
    DIRECTION INPUT ;
    USE SIGNAL ;
    SHAPE ABUTMENT ;
    PORT
      LAYER M3 ;
      RECT 0 72.695 0.07 72.765 ;
    END
  END rw0_wd_in[165]
  PIN rw0_wd_in[166]
    DIRECTION INPUT ;
    USE SIGNAL ;
    SHAPE ABUTMENT ;
    PORT
      LAYER M3 ;
      RECT 0 73.115 0.07 73.185 ;
    END
  END rw0_wd_in[166]
  PIN rw0_wd_in[167]
    DIRECTION INPUT ;
    USE SIGNAL ;
    SHAPE ABUTMENT ;
    PORT
      LAYER M3 ;
      RECT 0 73.535 0.07 73.605 ;
    END
  END rw0_wd_in[167]
  PIN rw0_wd_in[168]
    DIRECTION INPUT ;
    USE SIGNAL ;
    SHAPE ABUTMENT ;
    PORT
      LAYER M3 ;
      RECT 0 73.955 0.07 74.025 ;
    END
  END rw0_wd_in[168]
  PIN rw0_wd_in[169]
    DIRECTION INPUT ;
    USE SIGNAL ;
    SHAPE ABUTMENT ;
    PORT
      LAYER M3 ;
      RECT 0 74.375 0.07 74.445 ;
    END
  END rw0_wd_in[169]
  PIN rw0_wd_in[170]
    DIRECTION INPUT ;
    USE SIGNAL ;
    SHAPE ABUTMENT ;
    PORT
      LAYER M3 ;
      RECT 0 74.795 0.07 74.865 ;
    END
  END rw0_wd_in[170]
  PIN rw0_wd_in[171]
    DIRECTION INPUT ;
    USE SIGNAL ;
    SHAPE ABUTMENT ;
    PORT
      LAYER M3 ;
      RECT 0 75.215 0.07 75.285 ;
    END
  END rw0_wd_in[171]
  PIN rw0_wd_in[172]
    DIRECTION INPUT ;
    USE SIGNAL ;
    SHAPE ABUTMENT ;
    PORT
      LAYER M3 ;
      RECT 0 75.635 0.07 75.705 ;
    END
  END rw0_wd_in[172]
  PIN rw0_wd_in[173]
    DIRECTION INPUT ;
    USE SIGNAL ;
    SHAPE ABUTMENT ;
    PORT
      LAYER M3 ;
      RECT 0 76.055 0.07 76.125 ;
    END
  END rw0_wd_in[173]
  PIN rw0_wd_in[174]
    DIRECTION INPUT ;
    USE SIGNAL ;
    SHAPE ABUTMENT ;
    PORT
      LAYER M3 ;
      RECT 0 76.475 0.07 76.545 ;
    END
  END rw0_wd_in[174]
  PIN rw0_wd_in[175]
    DIRECTION INPUT ;
    USE SIGNAL ;
    SHAPE ABUTMENT ;
    PORT
      LAYER M3 ;
      RECT 0 76.895 0.07 76.965 ;
    END
  END rw0_wd_in[175]
  PIN rw0_wd_in[176]
    DIRECTION INPUT ;
    USE SIGNAL ;
    SHAPE ABUTMENT ;
    PORT
      LAYER M3 ;
      RECT 0 77.315 0.07 77.385 ;
    END
  END rw0_wd_in[176]
  PIN rw0_wd_in[177]
    DIRECTION INPUT ;
    USE SIGNAL ;
    SHAPE ABUTMENT ;
    PORT
      LAYER M3 ;
      RECT 0 77.735 0.07 77.805 ;
    END
  END rw0_wd_in[177]
  PIN rw0_wd_in[178]
    DIRECTION INPUT ;
    USE SIGNAL ;
    SHAPE ABUTMENT ;
    PORT
      LAYER M3 ;
      RECT 0 78.155 0.07 78.225 ;
    END
  END rw0_wd_in[178]
  PIN rw0_wd_in[179]
    DIRECTION INPUT ;
    USE SIGNAL ;
    SHAPE ABUTMENT ;
    PORT
      LAYER M3 ;
      RECT 0 78.575 0.07 78.645 ;
    END
  END rw0_wd_in[179]
  PIN rw0_wd_in[180]
    DIRECTION INPUT ;
    USE SIGNAL ;
    SHAPE ABUTMENT ;
    PORT
      LAYER M3 ;
      RECT 0 78.995 0.07 79.065 ;
    END
  END rw0_wd_in[180]
  PIN rw0_wd_in[181]
    DIRECTION INPUT ;
    USE SIGNAL ;
    SHAPE ABUTMENT ;
    PORT
      LAYER M3 ;
      RECT 0 79.415 0.07 79.485 ;
    END
  END rw0_wd_in[181]
  PIN rw0_wd_in[182]
    DIRECTION INPUT ;
    USE SIGNAL ;
    SHAPE ABUTMENT ;
    PORT
      LAYER M3 ;
      RECT 0 79.835 0.07 79.905 ;
    END
  END rw0_wd_in[182]
  PIN rw0_wd_in[183]
    DIRECTION INPUT ;
    USE SIGNAL ;
    SHAPE ABUTMENT ;
    PORT
      LAYER M3 ;
      RECT 0 80.255 0.07 80.325 ;
    END
  END rw0_wd_in[183]
  PIN rw0_wd_in[184]
    DIRECTION INPUT ;
    USE SIGNAL ;
    SHAPE ABUTMENT ;
    PORT
      LAYER M3 ;
      RECT 0 80.675 0.07 80.745 ;
    END
  END rw0_wd_in[184]
  PIN rw0_wd_in[185]
    DIRECTION INPUT ;
    USE SIGNAL ;
    SHAPE ABUTMENT ;
    PORT
      LAYER M3 ;
      RECT 0 81.095 0.07 81.165 ;
    END
  END rw0_wd_in[185]
  PIN rw0_wd_in[186]
    DIRECTION INPUT ;
    USE SIGNAL ;
    SHAPE ABUTMENT ;
    PORT
      LAYER M3 ;
      RECT 0 81.515 0.07 81.585 ;
    END
  END rw0_wd_in[186]
  PIN rw0_wd_in[187]
    DIRECTION INPUT ;
    USE SIGNAL ;
    SHAPE ABUTMENT ;
    PORT
      LAYER M3 ;
      RECT 0 81.935 0.07 82.005 ;
    END
  END rw0_wd_in[187]
  PIN rw0_wd_in[188]
    DIRECTION INPUT ;
    USE SIGNAL ;
    SHAPE ABUTMENT ;
    PORT
      LAYER M3 ;
      RECT 0 82.355 0.07 82.425 ;
    END
  END rw0_wd_in[188]
  PIN rw0_wd_in[189]
    DIRECTION INPUT ;
    USE SIGNAL ;
    SHAPE ABUTMENT ;
    PORT
      LAYER M3 ;
      RECT 0 82.775 0.07 82.845 ;
    END
  END rw0_wd_in[189]
  PIN rw0_wd_in[190]
    DIRECTION INPUT ;
    USE SIGNAL ;
    SHAPE ABUTMENT ;
    PORT
      LAYER M3 ;
      RECT 0 83.195 0.07 83.265 ;
    END
  END rw0_wd_in[190]
  PIN rw0_wd_in[191]
    DIRECTION INPUT ;
    USE SIGNAL ;
    SHAPE ABUTMENT ;
    PORT
      LAYER M3 ;
      RECT 0 83.615 0.07 83.685 ;
    END
  END rw0_wd_in[191]
  PIN rw0_wd_in[192]
    DIRECTION INPUT ;
    USE SIGNAL ;
    SHAPE ABUTMENT ;
    PORT
      LAYER M3 ;
      RECT 0 84.035 0.07 84.105 ;
    END
  END rw0_wd_in[192]
  PIN rw0_wd_in[193]
    DIRECTION INPUT ;
    USE SIGNAL ;
    SHAPE ABUTMENT ;
    PORT
      LAYER M3 ;
      RECT 0 84.455 0.07 84.525 ;
    END
  END rw0_wd_in[193]
  PIN rw0_wd_in[194]
    DIRECTION INPUT ;
    USE SIGNAL ;
    SHAPE ABUTMENT ;
    PORT
      LAYER M3 ;
      RECT 0 84.875 0.07 84.945 ;
    END
  END rw0_wd_in[194]
  PIN rw0_wd_in[195]
    DIRECTION INPUT ;
    USE SIGNAL ;
    SHAPE ABUTMENT ;
    PORT
      LAYER M3 ;
      RECT 0 85.295 0.07 85.365 ;
    END
  END rw0_wd_in[195]
  PIN rw0_wd_in[196]
    DIRECTION INPUT ;
    USE SIGNAL ;
    SHAPE ABUTMENT ;
    PORT
      LAYER M3 ;
      RECT 0 85.715 0.07 85.785 ;
    END
  END rw0_wd_in[196]
  PIN rw0_wd_in[197]
    DIRECTION INPUT ;
    USE SIGNAL ;
    SHAPE ABUTMENT ;
    PORT
      LAYER M3 ;
      RECT 0 86.135 0.07 86.205 ;
    END
  END rw0_wd_in[197]
  PIN rw0_wd_in[198]
    DIRECTION INPUT ;
    USE SIGNAL ;
    SHAPE ABUTMENT ;
    PORT
      LAYER M3 ;
      RECT 0 86.555 0.07 86.625 ;
    END
  END rw0_wd_in[198]
  PIN rw0_wd_in[199]
    DIRECTION INPUT ;
    USE SIGNAL ;
    SHAPE ABUTMENT ;
    PORT
      LAYER M3 ;
      RECT 0 86.975 0.07 87.045 ;
    END
  END rw0_wd_in[199]
  PIN rw0_wd_in[200]
    DIRECTION INPUT ;
    USE SIGNAL ;
    SHAPE ABUTMENT ;
    PORT
      LAYER M3 ;
      RECT 0 87.395 0.07 87.465 ;
    END
  END rw0_wd_in[200]
  PIN rw0_wd_in[201]
    DIRECTION INPUT ;
    USE SIGNAL ;
    SHAPE ABUTMENT ;
    PORT
      LAYER M3 ;
      RECT 0 87.815 0.07 87.885 ;
    END
  END rw0_wd_in[201]
  PIN rw0_wd_in[202]
    DIRECTION INPUT ;
    USE SIGNAL ;
    SHAPE ABUTMENT ;
    PORT
      LAYER M3 ;
      RECT 0 88.235 0.07 88.305 ;
    END
  END rw0_wd_in[202]
  PIN rw0_wd_in[203]
    DIRECTION INPUT ;
    USE SIGNAL ;
    SHAPE ABUTMENT ;
    PORT
      LAYER M3 ;
      RECT 0 88.655 0.07 88.725 ;
    END
  END rw0_wd_in[203]
  PIN rw0_wd_in[204]
    DIRECTION INPUT ;
    USE SIGNAL ;
    SHAPE ABUTMENT ;
    PORT
      LAYER M3 ;
      RECT 0 89.075 0.07 89.145 ;
    END
  END rw0_wd_in[204]
  PIN rw0_wd_in[205]
    DIRECTION INPUT ;
    USE SIGNAL ;
    SHAPE ABUTMENT ;
    PORT
      LAYER M3 ;
      RECT 0 89.495 0.07 89.565 ;
    END
  END rw0_wd_in[205]
  PIN rw0_wd_in[206]
    DIRECTION INPUT ;
    USE SIGNAL ;
    SHAPE ABUTMENT ;
    PORT
      LAYER M3 ;
      RECT 0 89.915 0.07 89.985 ;
    END
  END rw0_wd_in[206]
  PIN rw0_wd_in[207]
    DIRECTION INPUT ;
    USE SIGNAL ;
    SHAPE ABUTMENT ;
    PORT
      LAYER M3 ;
      RECT 0 90.335 0.07 90.405 ;
    END
  END rw0_wd_in[207]
  PIN rw0_wd_in[208]
    DIRECTION INPUT ;
    USE SIGNAL ;
    SHAPE ABUTMENT ;
    PORT
      LAYER M3 ;
      RECT 0 90.755 0.07 90.825 ;
    END
  END rw0_wd_in[208]
  PIN rw0_wd_in[209]
    DIRECTION INPUT ;
    USE SIGNAL ;
    SHAPE ABUTMENT ;
    PORT
      LAYER M3 ;
      RECT 0 91.175 0.07 91.245 ;
    END
  END rw0_wd_in[209]
  PIN rw0_wd_in[210]
    DIRECTION INPUT ;
    USE SIGNAL ;
    SHAPE ABUTMENT ;
    PORT
      LAYER M3 ;
      RECT 0 91.595 0.07 91.665 ;
    END
  END rw0_wd_in[210]
  PIN rw0_wd_in[211]
    DIRECTION INPUT ;
    USE SIGNAL ;
    SHAPE ABUTMENT ;
    PORT
      LAYER M3 ;
      RECT 0 92.015 0.07 92.085 ;
    END
  END rw0_wd_in[211]
  PIN rw0_wd_in[212]
    DIRECTION INPUT ;
    USE SIGNAL ;
    SHAPE ABUTMENT ;
    PORT
      LAYER M3 ;
      RECT 0 92.435 0.07 92.505 ;
    END
  END rw0_wd_in[212]
  PIN rw0_wd_in[213]
    DIRECTION INPUT ;
    USE SIGNAL ;
    SHAPE ABUTMENT ;
    PORT
      LAYER M3 ;
      RECT 0 92.855 0.07 92.925 ;
    END
  END rw0_wd_in[213]
  PIN rw0_wd_in[214]
    DIRECTION INPUT ;
    USE SIGNAL ;
    SHAPE ABUTMENT ;
    PORT
      LAYER M3 ;
      RECT 0 93.275 0.07 93.345 ;
    END
  END rw0_wd_in[214]
  PIN rw0_wd_in[215]
    DIRECTION INPUT ;
    USE SIGNAL ;
    SHAPE ABUTMENT ;
    PORT
      LAYER M3 ;
      RECT 0 93.695 0.07 93.765 ;
    END
  END rw0_wd_in[215]
  PIN rw0_wd_in[216]
    DIRECTION INPUT ;
    USE SIGNAL ;
    SHAPE ABUTMENT ;
    PORT
      LAYER M3 ;
      RECT 0 94.115 0.07 94.185 ;
    END
  END rw0_wd_in[216]
  PIN rw0_wd_in[217]
    DIRECTION INPUT ;
    USE SIGNAL ;
    SHAPE ABUTMENT ;
    PORT
      LAYER M3 ;
      RECT 0 94.535 0.07 94.605 ;
    END
  END rw0_wd_in[217]
  PIN rw0_wd_in[218]
    DIRECTION INPUT ;
    USE SIGNAL ;
    SHAPE ABUTMENT ;
    PORT
      LAYER M3 ;
      RECT 0 94.955 0.07 95.025 ;
    END
  END rw0_wd_in[218]
  PIN rw0_wd_in[219]
    DIRECTION INPUT ;
    USE SIGNAL ;
    SHAPE ABUTMENT ;
    PORT
      LAYER M3 ;
      RECT 0 95.375 0.07 95.445 ;
    END
  END rw0_wd_in[219]
  PIN rw0_wd_in[220]
    DIRECTION INPUT ;
    USE SIGNAL ;
    SHAPE ABUTMENT ;
    PORT
      LAYER M3 ;
      RECT 0 95.795 0.07 95.865 ;
    END
  END rw0_wd_in[220]
  PIN rw0_wd_in[221]
    DIRECTION INPUT ;
    USE SIGNAL ;
    SHAPE ABUTMENT ;
    PORT
      LAYER M3 ;
      RECT 0 96.215 0.07 96.285 ;
    END
  END rw0_wd_in[221]
  PIN rw0_wd_in[222]
    DIRECTION INPUT ;
    USE SIGNAL ;
    SHAPE ABUTMENT ;
    PORT
      LAYER M3 ;
      RECT 0 96.635 0.07 96.705 ;
    END
  END rw0_wd_in[222]
  PIN rw0_wd_in[223]
    DIRECTION INPUT ;
    USE SIGNAL ;
    SHAPE ABUTMENT ;
    PORT
      LAYER M3 ;
      RECT 0 97.055 0.07 97.125 ;
    END
  END rw0_wd_in[223]
  PIN rw0_wd_in[224]
    DIRECTION INPUT ;
    USE SIGNAL ;
    SHAPE ABUTMENT ;
    PORT
      LAYER M3 ;
      RECT 0 97.475 0.07 97.545 ;
    END
  END rw0_wd_in[224]
  PIN rw0_wd_in[225]
    DIRECTION INPUT ;
    USE SIGNAL ;
    SHAPE ABUTMENT ;
    PORT
      LAYER M3 ;
      RECT 0 97.895 0.07 97.965 ;
    END
  END rw0_wd_in[225]
  PIN rw0_wd_in[226]
    DIRECTION INPUT ;
    USE SIGNAL ;
    SHAPE ABUTMENT ;
    PORT
      LAYER M3 ;
      RECT 0 98.315 0.07 98.385 ;
    END
  END rw0_wd_in[226]
  PIN rw0_wd_in[227]
    DIRECTION INPUT ;
    USE SIGNAL ;
    SHAPE ABUTMENT ;
    PORT
      LAYER M3 ;
      RECT 0 98.735 0.07 98.805 ;
    END
  END rw0_wd_in[227]
  PIN rw0_wd_in[228]
    DIRECTION INPUT ;
    USE SIGNAL ;
    SHAPE ABUTMENT ;
    PORT
      LAYER M3 ;
      RECT 0 99.155 0.07 99.225 ;
    END
  END rw0_wd_in[228]
  PIN rw0_wd_in[229]
    DIRECTION INPUT ;
    USE SIGNAL ;
    SHAPE ABUTMENT ;
    PORT
      LAYER M3 ;
      RECT 0 99.575 0.07 99.645 ;
    END
  END rw0_wd_in[229]
  PIN rw0_wd_in[230]
    DIRECTION INPUT ;
    USE SIGNAL ;
    SHAPE ABUTMENT ;
    PORT
      LAYER M3 ;
      RECT 0 99.995 0.07 100.065 ;
    END
  END rw0_wd_in[230]
  PIN rw0_wd_in[231]
    DIRECTION INPUT ;
    USE SIGNAL ;
    SHAPE ABUTMENT ;
    PORT
      LAYER M3 ;
      RECT 0 100.415 0.07 100.485 ;
    END
  END rw0_wd_in[231]
  PIN rw0_wd_in[232]
    DIRECTION INPUT ;
    USE SIGNAL ;
    SHAPE ABUTMENT ;
    PORT
      LAYER M3 ;
      RECT 0 100.835 0.07 100.905 ;
    END
  END rw0_wd_in[232]
  PIN rw0_wd_in[233]
    DIRECTION INPUT ;
    USE SIGNAL ;
    SHAPE ABUTMENT ;
    PORT
      LAYER M3 ;
      RECT 0 101.255 0.07 101.325 ;
    END
  END rw0_wd_in[233]
  PIN rw0_wd_in[234]
    DIRECTION INPUT ;
    USE SIGNAL ;
    SHAPE ABUTMENT ;
    PORT
      LAYER M3 ;
      RECT 0 101.675 0.07 101.745 ;
    END
  END rw0_wd_in[234]
  PIN rw0_wd_in[235]
    DIRECTION INPUT ;
    USE SIGNAL ;
    SHAPE ABUTMENT ;
    PORT
      LAYER M3 ;
      RECT 0 102.095 0.07 102.165 ;
    END
  END rw0_wd_in[235]
  PIN rw0_wd_in[236]
    DIRECTION INPUT ;
    USE SIGNAL ;
    SHAPE ABUTMENT ;
    PORT
      LAYER M3 ;
      RECT 0 102.515 0.07 102.585 ;
    END
  END rw0_wd_in[236]
  PIN rw0_wd_in[237]
    DIRECTION INPUT ;
    USE SIGNAL ;
    SHAPE ABUTMENT ;
    PORT
      LAYER M3 ;
      RECT 0 102.935 0.07 103.005 ;
    END
  END rw0_wd_in[237]
  PIN rw0_wd_in[238]
    DIRECTION INPUT ;
    USE SIGNAL ;
    SHAPE ABUTMENT ;
    PORT
      LAYER M3 ;
      RECT 0 103.355 0.07 103.425 ;
    END
  END rw0_wd_in[238]
  PIN rw0_wd_in[239]
    DIRECTION INPUT ;
    USE SIGNAL ;
    SHAPE ABUTMENT ;
    PORT
      LAYER M3 ;
      RECT 0 103.775 0.07 103.845 ;
    END
  END rw0_wd_in[239]
  PIN rw0_wd_in[240]
    DIRECTION INPUT ;
    USE SIGNAL ;
    SHAPE ABUTMENT ;
    PORT
      LAYER M3 ;
      RECT 0 104.195 0.07 104.265 ;
    END
  END rw0_wd_in[240]
  PIN rw0_wd_in[241]
    DIRECTION INPUT ;
    USE SIGNAL ;
    SHAPE ABUTMENT ;
    PORT
      LAYER M3 ;
      RECT 0 104.615 0.07 104.685 ;
    END
  END rw0_wd_in[241]
  PIN rw0_wd_in[242]
    DIRECTION INPUT ;
    USE SIGNAL ;
    SHAPE ABUTMENT ;
    PORT
      LAYER M3 ;
      RECT 0 105.035 0.07 105.105 ;
    END
  END rw0_wd_in[242]
  PIN rw0_wd_in[243]
    DIRECTION INPUT ;
    USE SIGNAL ;
    SHAPE ABUTMENT ;
    PORT
      LAYER M3 ;
      RECT 0 105.455 0.07 105.525 ;
    END
  END rw0_wd_in[243]
  PIN rw0_wd_in[244]
    DIRECTION INPUT ;
    USE SIGNAL ;
    SHAPE ABUTMENT ;
    PORT
      LAYER M3 ;
      RECT 0 105.875 0.07 105.945 ;
    END
  END rw0_wd_in[244]
  PIN rw0_wd_in[245]
    DIRECTION INPUT ;
    USE SIGNAL ;
    SHAPE ABUTMENT ;
    PORT
      LAYER M3 ;
      RECT 0 106.295 0.07 106.365 ;
    END
  END rw0_wd_in[245]
  PIN rw0_wd_in[246]
    DIRECTION INPUT ;
    USE SIGNAL ;
    SHAPE ABUTMENT ;
    PORT
      LAYER M3 ;
      RECT 0 106.715 0.07 106.785 ;
    END
  END rw0_wd_in[246]
  PIN rw0_wd_in[247]
    DIRECTION INPUT ;
    USE SIGNAL ;
    SHAPE ABUTMENT ;
    PORT
      LAYER M3 ;
      RECT 0 107.135 0.07 107.205 ;
    END
  END rw0_wd_in[247]
  PIN rw0_wd_in[248]
    DIRECTION INPUT ;
    USE SIGNAL ;
    SHAPE ABUTMENT ;
    PORT
      LAYER M3 ;
      RECT 0 107.555 0.07 107.625 ;
    END
  END rw0_wd_in[248]
  PIN rw0_wd_in[249]
    DIRECTION INPUT ;
    USE SIGNAL ;
    SHAPE ABUTMENT ;
    PORT
      LAYER M3 ;
      RECT 0 107.975 0.07 108.045 ;
    END
  END rw0_wd_in[249]
  PIN rw0_wd_in[250]
    DIRECTION INPUT ;
    USE SIGNAL ;
    SHAPE ABUTMENT ;
    PORT
      LAYER M3 ;
      RECT 0 108.395 0.07 108.465 ;
    END
  END rw0_wd_in[250]
  PIN rw0_wd_in[251]
    DIRECTION INPUT ;
    USE SIGNAL ;
    SHAPE ABUTMENT ;
    PORT
      LAYER M3 ;
      RECT 0 108.815 0.07 108.885 ;
    END
  END rw0_wd_in[251]
  PIN rw0_wd_in[252]
    DIRECTION INPUT ;
    USE SIGNAL ;
    SHAPE ABUTMENT ;
    PORT
      LAYER M3 ;
      RECT 0 109.235 0.07 109.305 ;
    END
  END rw0_wd_in[252]
  PIN rw0_wd_in[253]
    DIRECTION INPUT ;
    USE SIGNAL ;
    SHAPE ABUTMENT ;
    PORT
      LAYER M3 ;
      RECT 0 109.655 0.07 109.725 ;
    END
  END rw0_wd_in[253]
  PIN rw0_wd_in[254]
    DIRECTION INPUT ;
    USE SIGNAL ;
    SHAPE ABUTMENT ;
    PORT
      LAYER M3 ;
      RECT 0 110.075 0.07 110.145 ;
    END
  END rw0_wd_in[254]
  PIN rw0_wd_in[255]
    DIRECTION INPUT ;
    USE SIGNAL ;
    SHAPE ABUTMENT ;
    PORT
      LAYER M3 ;
      RECT 0 110.495 0.07 110.565 ;
    END
  END rw0_wd_in[255]
  PIN rw0_rd_out[0]
    DIRECTION OUTPUT ;
    USE SIGNAL ;
    SHAPE ABUTMENT ;
    PORT
      LAYER M3 ;
      RECT 0 110.915 0.07 110.985 ;
    END
  END rw0_rd_out[0]
  PIN rw0_rd_out[1]
    DIRECTION OUTPUT ;
    USE SIGNAL ;
    SHAPE ABUTMENT ;
    PORT
      LAYER M3 ;
      RECT 0 111.335 0.07 111.405 ;
    END
  END rw0_rd_out[1]
  PIN rw0_rd_out[2]
    DIRECTION OUTPUT ;
    USE SIGNAL ;
    SHAPE ABUTMENT ;
    PORT
      LAYER M3 ;
      RECT 0 111.755 0.07 111.825 ;
    END
  END rw0_rd_out[2]
  PIN rw0_rd_out[3]
    DIRECTION OUTPUT ;
    USE SIGNAL ;
    SHAPE ABUTMENT ;
    PORT
      LAYER M3 ;
      RECT 0 112.175 0.07 112.245 ;
    END
  END rw0_rd_out[3]
  PIN rw0_rd_out[4]
    DIRECTION OUTPUT ;
    USE SIGNAL ;
    SHAPE ABUTMENT ;
    PORT
      LAYER M3 ;
      RECT 0 112.595 0.07 112.665 ;
    END
  END rw0_rd_out[4]
  PIN rw0_rd_out[5]
    DIRECTION OUTPUT ;
    USE SIGNAL ;
    SHAPE ABUTMENT ;
    PORT
      LAYER M3 ;
      RECT 0 113.015 0.07 113.085 ;
    END
  END rw0_rd_out[5]
  PIN rw0_rd_out[6]
    DIRECTION OUTPUT ;
    USE SIGNAL ;
    SHAPE ABUTMENT ;
    PORT
      LAYER M3 ;
      RECT 0 113.435 0.07 113.505 ;
    END
  END rw0_rd_out[6]
  PIN rw0_rd_out[7]
    DIRECTION OUTPUT ;
    USE SIGNAL ;
    SHAPE ABUTMENT ;
    PORT
      LAYER M3 ;
      RECT 0 113.855 0.07 113.925 ;
    END
  END rw0_rd_out[7]
  PIN rw0_rd_out[8]
    DIRECTION OUTPUT ;
    USE SIGNAL ;
    SHAPE ABUTMENT ;
    PORT
      LAYER M3 ;
      RECT 0 114.275 0.07 114.345 ;
    END
  END rw0_rd_out[8]
  PIN rw0_rd_out[9]
    DIRECTION OUTPUT ;
    USE SIGNAL ;
    SHAPE ABUTMENT ;
    PORT
      LAYER M3 ;
      RECT 0 114.695 0.07 114.765 ;
    END
  END rw0_rd_out[9]
  PIN rw0_rd_out[10]
    DIRECTION OUTPUT ;
    USE SIGNAL ;
    SHAPE ABUTMENT ;
    PORT
      LAYER M3 ;
      RECT 0 115.115 0.07 115.185 ;
    END
  END rw0_rd_out[10]
  PIN rw0_rd_out[11]
    DIRECTION OUTPUT ;
    USE SIGNAL ;
    SHAPE ABUTMENT ;
    PORT
      LAYER M3 ;
      RECT 0 115.535 0.07 115.605 ;
    END
  END rw0_rd_out[11]
  PIN rw0_rd_out[12]
    DIRECTION OUTPUT ;
    USE SIGNAL ;
    SHAPE ABUTMENT ;
    PORT
      LAYER M3 ;
      RECT 0 115.955 0.07 116.025 ;
    END
  END rw0_rd_out[12]
  PIN rw0_rd_out[13]
    DIRECTION OUTPUT ;
    USE SIGNAL ;
    SHAPE ABUTMENT ;
    PORT
      LAYER M3 ;
      RECT 0 116.375 0.07 116.445 ;
    END
  END rw0_rd_out[13]
  PIN rw0_rd_out[14]
    DIRECTION OUTPUT ;
    USE SIGNAL ;
    SHAPE ABUTMENT ;
    PORT
      LAYER M3 ;
      RECT 0 116.795 0.07 116.865 ;
    END
  END rw0_rd_out[14]
  PIN rw0_rd_out[15]
    DIRECTION OUTPUT ;
    USE SIGNAL ;
    SHAPE ABUTMENT ;
    PORT
      LAYER M3 ;
      RECT 0 117.215 0.07 117.285 ;
    END
  END rw0_rd_out[15]
  PIN rw0_rd_out[16]
    DIRECTION OUTPUT ;
    USE SIGNAL ;
    SHAPE ABUTMENT ;
    PORT
      LAYER M3 ;
      RECT 0 117.635 0.07 117.705 ;
    END
  END rw0_rd_out[16]
  PIN rw0_rd_out[17]
    DIRECTION OUTPUT ;
    USE SIGNAL ;
    SHAPE ABUTMENT ;
    PORT
      LAYER M3 ;
      RECT 0 118.055 0.07 118.125 ;
    END
  END rw0_rd_out[17]
  PIN rw0_rd_out[18]
    DIRECTION OUTPUT ;
    USE SIGNAL ;
    SHAPE ABUTMENT ;
    PORT
      LAYER M3 ;
      RECT 0 118.475 0.07 118.545 ;
    END
  END rw0_rd_out[18]
  PIN rw0_rd_out[19]
    DIRECTION OUTPUT ;
    USE SIGNAL ;
    SHAPE ABUTMENT ;
    PORT
      LAYER M3 ;
      RECT 0 118.895 0.07 118.965 ;
    END
  END rw0_rd_out[19]
  PIN rw0_rd_out[20]
    DIRECTION OUTPUT ;
    USE SIGNAL ;
    SHAPE ABUTMENT ;
    PORT
      LAYER M3 ;
      RECT 0 119.315 0.07 119.385 ;
    END
  END rw0_rd_out[20]
  PIN rw0_rd_out[21]
    DIRECTION OUTPUT ;
    USE SIGNAL ;
    SHAPE ABUTMENT ;
    PORT
      LAYER M3 ;
      RECT 0 119.735 0.07 119.805 ;
    END
  END rw0_rd_out[21]
  PIN rw0_rd_out[22]
    DIRECTION OUTPUT ;
    USE SIGNAL ;
    SHAPE ABUTMENT ;
    PORT
      LAYER M3 ;
      RECT 0 120.155 0.07 120.225 ;
    END
  END rw0_rd_out[22]
  PIN rw0_rd_out[23]
    DIRECTION OUTPUT ;
    USE SIGNAL ;
    SHAPE ABUTMENT ;
    PORT
      LAYER M3 ;
      RECT 0 120.575 0.07 120.645 ;
    END
  END rw0_rd_out[23]
  PIN rw0_rd_out[24]
    DIRECTION OUTPUT ;
    USE SIGNAL ;
    SHAPE ABUTMENT ;
    PORT
      LAYER M3 ;
      RECT 0 120.995 0.07 121.065 ;
    END
  END rw0_rd_out[24]
  PIN rw0_rd_out[25]
    DIRECTION OUTPUT ;
    USE SIGNAL ;
    SHAPE ABUTMENT ;
    PORT
      LAYER M3 ;
      RECT 0 121.415 0.07 121.485 ;
    END
  END rw0_rd_out[25]
  PIN rw0_rd_out[26]
    DIRECTION OUTPUT ;
    USE SIGNAL ;
    SHAPE ABUTMENT ;
    PORT
      LAYER M3 ;
      RECT 0 121.835 0.07 121.905 ;
    END
  END rw0_rd_out[26]
  PIN rw0_rd_out[27]
    DIRECTION OUTPUT ;
    USE SIGNAL ;
    SHAPE ABUTMENT ;
    PORT
      LAYER M3 ;
      RECT 0 122.255 0.07 122.325 ;
    END
  END rw0_rd_out[27]
  PIN rw0_rd_out[28]
    DIRECTION OUTPUT ;
    USE SIGNAL ;
    SHAPE ABUTMENT ;
    PORT
      LAYER M3 ;
      RECT 0 122.675 0.07 122.745 ;
    END
  END rw0_rd_out[28]
  PIN rw0_rd_out[29]
    DIRECTION OUTPUT ;
    USE SIGNAL ;
    SHAPE ABUTMENT ;
    PORT
      LAYER M3 ;
      RECT 0 123.095 0.07 123.165 ;
    END
  END rw0_rd_out[29]
  PIN rw0_rd_out[30]
    DIRECTION OUTPUT ;
    USE SIGNAL ;
    SHAPE ABUTMENT ;
    PORT
      LAYER M3 ;
      RECT 0 123.515 0.07 123.585 ;
    END
  END rw0_rd_out[30]
  PIN rw0_rd_out[31]
    DIRECTION OUTPUT ;
    USE SIGNAL ;
    SHAPE ABUTMENT ;
    PORT
      LAYER M3 ;
      RECT 0 123.935 0.07 124.005 ;
    END
  END rw0_rd_out[31]
  PIN rw0_rd_out[32]
    DIRECTION OUTPUT ;
    USE SIGNAL ;
    SHAPE ABUTMENT ;
    PORT
      LAYER M3 ;
      RECT 0 124.355 0.07 124.425 ;
    END
  END rw0_rd_out[32]
  PIN rw0_rd_out[33]
    DIRECTION OUTPUT ;
    USE SIGNAL ;
    SHAPE ABUTMENT ;
    PORT
      LAYER M3 ;
      RECT 0 124.775 0.07 124.845 ;
    END
  END rw0_rd_out[33]
  PIN rw0_rd_out[34]
    DIRECTION OUTPUT ;
    USE SIGNAL ;
    SHAPE ABUTMENT ;
    PORT
      LAYER M3 ;
      RECT 0 125.195 0.07 125.265 ;
    END
  END rw0_rd_out[34]
  PIN rw0_rd_out[35]
    DIRECTION OUTPUT ;
    USE SIGNAL ;
    SHAPE ABUTMENT ;
    PORT
      LAYER M3 ;
      RECT 0 125.615 0.07 125.685 ;
    END
  END rw0_rd_out[35]
  PIN rw0_rd_out[36]
    DIRECTION OUTPUT ;
    USE SIGNAL ;
    SHAPE ABUTMENT ;
    PORT
      LAYER M3 ;
      RECT 0 126.035 0.07 126.105 ;
    END
  END rw0_rd_out[36]
  PIN rw0_rd_out[37]
    DIRECTION OUTPUT ;
    USE SIGNAL ;
    SHAPE ABUTMENT ;
    PORT
      LAYER M3 ;
      RECT 0 126.455 0.07 126.525 ;
    END
  END rw0_rd_out[37]
  PIN rw0_rd_out[38]
    DIRECTION OUTPUT ;
    USE SIGNAL ;
    SHAPE ABUTMENT ;
    PORT
      LAYER M3 ;
      RECT 0 126.875 0.07 126.945 ;
    END
  END rw0_rd_out[38]
  PIN rw0_rd_out[39]
    DIRECTION OUTPUT ;
    USE SIGNAL ;
    SHAPE ABUTMENT ;
    PORT
      LAYER M3 ;
      RECT 0 127.295 0.07 127.365 ;
    END
  END rw0_rd_out[39]
  PIN rw0_rd_out[40]
    DIRECTION OUTPUT ;
    USE SIGNAL ;
    SHAPE ABUTMENT ;
    PORT
      LAYER M3 ;
      RECT 0 127.715 0.07 127.785 ;
    END
  END rw0_rd_out[40]
  PIN rw0_rd_out[41]
    DIRECTION OUTPUT ;
    USE SIGNAL ;
    SHAPE ABUTMENT ;
    PORT
      LAYER M3 ;
      RECT 0 128.135 0.07 128.205 ;
    END
  END rw0_rd_out[41]
  PIN rw0_rd_out[42]
    DIRECTION OUTPUT ;
    USE SIGNAL ;
    SHAPE ABUTMENT ;
    PORT
      LAYER M3 ;
      RECT 0 128.555 0.07 128.625 ;
    END
  END rw0_rd_out[42]
  PIN rw0_rd_out[43]
    DIRECTION OUTPUT ;
    USE SIGNAL ;
    SHAPE ABUTMENT ;
    PORT
      LAYER M3 ;
      RECT 0 128.975 0.07 129.045 ;
    END
  END rw0_rd_out[43]
  PIN rw0_rd_out[44]
    DIRECTION OUTPUT ;
    USE SIGNAL ;
    SHAPE ABUTMENT ;
    PORT
      LAYER M3 ;
      RECT 0 129.395 0.07 129.465 ;
    END
  END rw0_rd_out[44]
  PIN rw0_rd_out[45]
    DIRECTION OUTPUT ;
    USE SIGNAL ;
    SHAPE ABUTMENT ;
    PORT
      LAYER M3 ;
      RECT 0 129.815 0.07 129.885 ;
    END
  END rw0_rd_out[45]
  PIN rw0_rd_out[46]
    DIRECTION OUTPUT ;
    USE SIGNAL ;
    SHAPE ABUTMENT ;
    PORT
      LAYER M3 ;
      RECT 0 130.235 0.07 130.305 ;
    END
  END rw0_rd_out[46]
  PIN rw0_rd_out[47]
    DIRECTION OUTPUT ;
    USE SIGNAL ;
    SHAPE ABUTMENT ;
    PORT
      LAYER M3 ;
      RECT 0 130.655 0.07 130.725 ;
    END
  END rw0_rd_out[47]
  PIN rw0_rd_out[48]
    DIRECTION OUTPUT ;
    USE SIGNAL ;
    SHAPE ABUTMENT ;
    PORT
      LAYER M3 ;
      RECT 0 131.075 0.07 131.145 ;
    END
  END rw0_rd_out[48]
  PIN rw0_rd_out[49]
    DIRECTION OUTPUT ;
    USE SIGNAL ;
    SHAPE ABUTMENT ;
    PORT
      LAYER M3 ;
      RECT 0 131.495 0.07 131.565 ;
    END
  END rw0_rd_out[49]
  PIN rw0_rd_out[50]
    DIRECTION OUTPUT ;
    USE SIGNAL ;
    SHAPE ABUTMENT ;
    PORT
      LAYER M3 ;
      RECT 0 131.915 0.07 131.985 ;
    END
  END rw0_rd_out[50]
  PIN rw0_rd_out[51]
    DIRECTION OUTPUT ;
    USE SIGNAL ;
    SHAPE ABUTMENT ;
    PORT
      LAYER M3 ;
      RECT 0 132.335 0.07 132.405 ;
    END
  END rw0_rd_out[51]
  PIN rw0_rd_out[52]
    DIRECTION OUTPUT ;
    USE SIGNAL ;
    SHAPE ABUTMENT ;
    PORT
      LAYER M3 ;
      RECT 0 132.755 0.07 132.825 ;
    END
  END rw0_rd_out[52]
  PIN rw0_rd_out[53]
    DIRECTION OUTPUT ;
    USE SIGNAL ;
    SHAPE ABUTMENT ;
    PORT
      LAYER M3 ;
      RECT 0 133.175 0.07 133.245 ;
    END
  END rw0_rd_out[53]
  PIN rw0_rd_out[54]
    DIRECTION OUTPUT ;
    USE SIGNAL ;
    SHAPE ABUTMENT ;
    PORT
      LAYER M3 ;
      RECT 0 133.595 0.07 133.665 ;
    END
  END rw0_rd_out[54]
  PIN rw0_rd_out[55]
    DIRECTION OUTPUT ;
    USE SIGNAL ;
    SHAPE ABUTMENT ;
    PORT
      LAYER M3 ;
      RECT 0 134.015 0.07 134.085 ;
    END
  END rw0_rd_out[55]
  PIN rw0_rd_out[56]
    DIRECTION OUTPUT ;
    USE SIGNAL ;
    SHAPE ABUTMENT ;
    PORT
      LAYER M3 ;
      RECT 0 134.435 0.07 134.505 ;
    END
  END rw0_rd_out[56]
  PIN rw0_rd_out[57]
    DIRECTION OUTPUT ;
    USE SIGNAL ;
    SHAPE ABUTMENT ;
    PORT
      LAYER M3 ;
      RECT 0 134.855 0.07 134.925 ;
    END
  END rw0_rd_out[57]
  PIN rw0_rd_out[58]
    DIRECTION OUTPUT ;
    USE SIGNAL ;
    SHAPE ABUTMENT ;
    PORT
      LAYER M3 ;
      RECT 0 135.275 0.07 135.345 ;
    END
  END rw0_rd_out[58]
  PIN rw0_rd_out[59]
    DIRECTION OUTPUT ;
    USE SIGNAL ;
    SHAPE ABUTMENT ;
    PORT
      LAYER M3 ;
      RECT 0 135.695 0.07 135.765 ;
    END
  END rw0_rd_out[59]
  PIN rw0_rd_out[60]
    DIRECTION OUTPUT ;
    USE SIGNAL ;
    SHAPE ABUTMENT ;
    PORT
      LAYER M3 ;
      RECT 0 136.115 0.07 136.185 ;
    END
  END rw0_rd_out[60]
  PIN rw0_rd_out[61]
    DIRECTION OUTPUT ;
    USE SIGNAL ;
    SHAPE ABUTMENT ;
    PORT
      LAYER M3 ;
      RECT 0 136.535 0.07 136.605 ;
    END
  END rw0_rd_out[61]
  PIN rw0_rd_out[62]
    DIRECTION OUTPUT ;
    USE SIGNAL ;
    SHAPE ABUTMENT ;
    PORT
      LAYER M3 ;
      RECT 0 136.955 0.07 137.025 ;
    END
  END rw0_rd_out[62]
  PIN rw0_rd_out[63]
    DIRECTION OUTPUT ;
    USE SIGNAL ;
    SHAPE ABUTMENT ;
    PORT
      LAYER M3 ;
      RECT 0 137.375 0.07 137.445 ;
    END
  END rw0_rd_out[63]
  PIN rw0_rd_out[64]
    DIRECTION OUTPUT ;
    USE SIGNAL ;
    SHAPE ABUTMENT ;
    PORT
      LAYER M3 ;
      RECT 0 137.795 0.07 137.865 ;
    END
  END rw0_rd_out[64]
  PIN rw0_rd_out[65]
    DIRECTION OUTPUT ;
    USE SIGNAL ;
    SHAPE ABUTMENT ;
    PORT
      LAYER M3 ;
      RECT 0 138.215 0.07 138.285 ;
    END
  END rw0_rd_out[65]
  PIN rw0_rd_out[66]
    DIRECTION OUTPUT ;
    USE SIGNAL ;
    SHAPE ABUTMENT ;
    PORT
      LAYER M3 ;
      RECT 0 138.635 0.07 138.705 ;
    END
  END rw0_rd_out[66]
  PIN rw0_rd_out[67]
    DIRECTION OUTPUT ;
    USE SIGNAL ;
    SHAPE ABUTMENT ;
    PORT
      LAYER M3 ;
      RECT 0 139.055 0.07 139.125 ;
    END
  END rw0_rd_out[67]
  PIN rw0_rd_out[68]
    DIRECTION OUTPUT ;
    USE SIGNAL ;
    SHAPE ABUTMENT ;
    PORT
      LAYER M3 ;
      RECT 0 139.475 0.07 139.545 ;
    END
  END rw0_rd_out[68]
  PIN rw0_rd_out[69]
    DIRECTION OUTPUT ;
    USE SIGNAL ;
    SHAPE ABUTMENT ;
    PORT
      LAYER M3 ;
      RECT 0 139.895 0.07 139.965 ;
    END
  END rw0_rd_out[69]
  PIN rw0_rd_out[70]
    DIRECTION OUTPUT ;
    USE SIGNAL ;
    SHAPE ABUTMENT ;
    PORT
      LAYER M3 ;
      RECT 0 140.315 0.07 140.385 ;
    END
  END rw0_rd_out[70]
  PIN rw0_rd_out[71]
    DIRECTION OUTPUT ;
    USE SIGNAL ;
    SHAPE ABUTMENT ;
    PORT
      LAYER M3 ;
      RECT 0 140.735 0.07 140.805 ;
    END
  END rw0_rd_out[71]
  PIN rw0_rd_out[72]
    DIRECTION OUTPUT ;
    USE SIGNAL ;
    SHAPE ABUTMENT ;
    PORT
      LAYER M3 ;
      RECT 0 141.155 0.07 141.225 ;
    END
  END rw0_rd_out[72]
  PIN rw0_rd_out[73]
    DIRECTION OUTPUT ;
    USE SIGNAL ;
    SHAPE ABUTMENT ;
    PORT
      LAYER M3 ;
      RECT 0 141.575 0.07 141.645 ;
    END
  END rw0_rd_out[73]
  PIN rw0_rd_out[74]
    DIRECTION OUTPUT ;
    USE SIGNAL ;
    SHAPE ABUTMENT ;
    PORT
      LAYER M3 ;
      RECT 0 141.995 0.07 142.065 ;
    END
  END rw0_rd_out[74]
  PIN rw0_rd_out[75]
    DIRECTION OUTPUT ;
    USE SIGNAL ;
    SHAPE ABUTMENT ;
    PORT
      LAYER M3 ;
      RECT 0 142.415 0.07 142.485 ;
    END
  END rw0_rd_out[75]
  PIN rw0_rd_out[76]
    DIRECTION OUTPUT ;
    USE SIGNAL ;
    SHAPE ABUTMENT ;
    PORT
      LAYER M3 ;
      RECT 0 142.835 0.07 142.905 ;
    END
  END rw0_rd_out[76]
  PIN rw0_rd_out[77]
    DIRECTION OUTPUT ;
    USE SIGNAL ;
    SHAPE ABUTMENT ;
    PORT
      LAYER M3 ;
      RECT 0 143.255 0.07 143.325 ;
    END
  END rw0_rd_out[77]
  PIN rw0_rd_out[78]
    DIRECTION OUTPUT ;
    USE SIGNAL ;
    SHAPE ABUTMENT ;
    PORT
      LAYER M3 ;
      RECT 0 143.675 0.07 143.745 ;
    END
  END rw0_rd_out[78]
  PIN rw0_rd_out[79]
    DIRECTION OUTPUT ;
    USE SIGNAL ;
    SHAPE ABUTMENT ;
    PORT
      LAYER M3 ;
      RECT 0 144.095 0.07 144.165 ;
    END
  END rw0_rd_out[79]
  PIN rw0_rd_out[80]
    DIRECTION OUTPUT ;
    USE SIGNAL ;
    SHAPE ABUTMENT ;
    PORT
      LAYER M3 ;
      RECT 0 144.515 0.07 144.585 ;
    END
  END rw0_rd_out[80]
  PIN rw0_rd_out[81]
    DIRECTION OUTPUT ;
    USE SIGNAL ;
    SHAPE ABUTMENT ;
    PORT
      LAYER M3 ;
      RECT 0 144.935 0.07 145.005 ;
    END
  END rw0_rd_out[81]
  PIN rw0_rd_out[82]
    DIRECTION OUTPUT ;
    USE SIGNAL ;
    SHAPE ABUTMENT ;
    PORT
      LAYER M3 ;
      RECT 0 145.355 0.07 145.425 ;
    END
  END rw0_rd_out[82]
  PIN rw0_rd_out[83]
    DIRECTION OUTPUT ;
    USE SIGNAL ;
    SHAPE ABUTMENT ;
    PORT
      LAYER M3 ;
      RECT 0 145.775 0.07 145.845 ;
    END
  END rw0_rd_out[83]
  PIN rw0_rd_out[84]
    DIRECTION OUTPUT ;
    USE SIGNAL ;
    SHAPE ABUTMENT ;
    PORT
      LAYER M3 ;
      RECT 0 146.195 0.07 146.265 ;
    END
  END rw0_rd_out[84]
  PIN rw0_rd_out[85]
    DIRECTION OUTPUT ;
    USE SIGNAL ;
    SHAPE ABUTMENT ;
    PORT
      LAYER M3 ;
      RECT 0 146.615 0.07 146.685 ;
    END
  END rw0_rd_out[85]
  PIN rw0_rd_out[86]
    DIRECTION OUTPUT ;
    USE SIGNAL ;
    SHAPE ABUTMENT ;
    PORT
      LAYER M3 ;
      RECT 0 147.035 0.07 147.105 ;
    END
  END rw0_rd_out[86]
  PIN rw0_rd_out[87]
    DIRECTION OUTPUT ;
    USE SIGNAL ;
    SHAPE ABUTMENT ;
    PORT
      LAYER M3 ;
      RECT 0 147.455 0.07 147.525 ;
    END
  END rw0_rd_out[87]
  PIN rw0_rd_out[88]
    DIRECTION OUTPUT ;
    USE SIGNAL ;
    SHAPE ABUTMENT ;
    PORT
      LAYER M3 ;
      RECT 0 147.875 0.07 147.945 ;
    END
  END rw0_rd_out[88]
  PIN rw0_rd_out[89]
    DIRECTION OUTPUT ;
    USE SIGNAL ;
    SHAPE ABUTMENT ;
    PORT
      LAYER M3 ;
      RECT 0 148.295 0.07 148.365 ;
    END
  END rw0_rd_out[89]
  PIN rw0_rd_out[90]
    DIRECTION OUTPUT ;
    USE SIGNAL ;
    SHAPE ABUTMENT ;
    PORT
      LAYER M3 ;
      RECT 0 148.715 0.07 148.785 ;
    END
  END rw0_rd_out[90]
  PIN rw0_rd_out[91]
    DIRECTION OUTPUT ;
    USE SIGNAL ;
    SHAPE ABUTMENT ;
    PORT
      LAYER M3 ;
      RECT 0 149.135 0.07 149.205 ;
    END
  END rw0_rd_out[91]
  PIN rw0_rd_out[92]
    DIRECTION OUTPUT ;
    USE SIGNAL ;
    SHAPE ABUTMENT ;
    PORT
      LAYER M3 ;
      RECT 0 149.555 0.07 149.625 ;
    END
  END rw0_rd_out[92]
  PIN rw0_rd_out[93]
    DIRECTION OUTPUT ;
    USE SIGNAL ;
    SHAPE ABUTMENT ;
    PORT
      LAYER M3 ;
      RECT 0 149.975 0.07 150.045 ;
    END
  END rw0_rd_out[93]
  PIN rw0_rd_out[94]
    DIRECTION OUTPUT ;
    USE SIGNAL ;
    SHAPE ABUTMENT ;
    PORT
      LAYER M3 ;
      RECT 0 150.395 0.07 150.465 ;
    END
  END rw0_rd_out[94]
  PIN rw0_rd_out[95]
    DIRECTION OUTPUT ;
    USE SIGNAL ;
    SHAPE ABUTMENT ;
    PORT
      LAYER M3 ;
      RECT 0 150.815 0.07 150.885 ;
    END
  END rw0_rd_out[95]
  PIN rw0_rd_out[96]
    DIRECTION OUTPUT ;
    USE SIGNAL ;
    SHAPE ABUTMENT ;
    PORT
      LAYER M3 ;
      RECT 0 151.235 0.07 151.305 ;
    END
  END rw0_rd_out[96]
  PIN rw0_rd_out[97]
    DIRECTION OUTPUT ;
    USE SIGNAL ;
    SHAPE ABUTMENT ;
    PORT
      LAYER M3 ;
      RECT 0 151.655 0.07 151.725 ;
    END
  END rw0_rd_out[97]
  PIN rw0_rd_out[98]
    DIRECTION OUTPUT ;
    USE SIGNAL ;
    SHAPE ABUTMENT ;
    PORT
      LAYER M3 ;
      RECT 0 152.075 0.07 152.145 ;
    END
  END rw0_rd_out[98]
  PIN rw0_rd_out[99]
    DIRECTION OUTPUT ;
    USE SIGNAL ;
    SHAPE ABUTMENT ;
    PORT
      LAYER M3 ;
      RECT 0 152.495 0.07 152.565 ;
    END
  END rw0_rd_out[99]
  PIN rw0_rd_out[100]
    DIRECTION OUTPUT ;
    USE SIGNAL ;
    SHAPE ABUTMENT ;
    PORT
      LAYER M3 ;
      RECT 0 152.915 0.07 152.985 ;
    END
  END rw0_rd_out[100]
  PIN rw0_rd_out[101]
    DIRECTION OUTPUT ;
    USE SIGNAL ;
    SHAPE ABUTMENT ;
    PORT
      LAYER M3 ;
      RECT 0 153.335 0.07 153.405 ;
    END
  END rw0_rd_out[101]
  PIN rw0_rd_out[102]
    DIRECTION OUTPUT ;
    USE SIGNAL ;
    SHAPE ABUTMENT ;
    PORT
      LAYER M3 ;
      RECT 0 153.755 0.07 153.825 ;
    END
  END rw0_rd_out[102]
  PIN rw0_rd_out[103]
    DIRECTION OUTPUT ;
    USE SIGNAL ;
    SHAPE ABUTMENT ;
    PORT
      LAYER M3 ;
      RECT 0 154.175 0.07 154.245 ;
    END
  END rw0_rd_out[103]
  PIN rw0_rd_out[104]
    DIRECTION OUTPUT ;
    USE SIGNAL ;
    SHAPE ABUTMENT ;
    PORT
      LAYER M3 ;
      RECT 0 154.595 0.07 154.665 ;
    END
  END rw0_rd_out[104]
  PIN rw0_rd_out[105]
    DIRECTION OUTPUT ;
    USE SIGNAL ;
    SHAPE ABUTMENT ;
    PORT
      LAYER M3 ;
      RECT 0 155.015 0.07 155.085 ;
    END
  END rw0_rd_out[105]
  PIN rw0_rd_out[106]
    DIRECTION OUTPUT ;
    USE SIGNAL ;
    SHAPE ABUTMENT ;
    PORT
      LAYER M3 ;
      RECT 0 155.435 0.07 155.505 ;
    END
  END rw0_rd_out[106]
  PIN rw0_rd_out[107]
    DIRECTION OUTPUT ;
    USE SIGNAL ;
    SHAPE ABUTMENT ;
    PORT
      LAYER M3 ;
      RECT 0 155.855 0.07 155.925 ;
    END
  END rw0_rd_out[107]
  PIN rw0_rd_out[108]
    DIRECTION OUTPUT ;
    USE SIGNAL ;
    SHAPE ABUTMENT ;
    PORT
      LAYER M3 ;
      RECT 0 156.275 0.07 156.345 ;
    END
  END rw0_rd_out[108]
  PIN rw0_rd_out[109]
    DIRECTION OUTPUT ;
    USE SIGNAL ;
    SHAPE ABUTMENT ;
    PORT
      LAYER M3 ;
      RECT 0 156.695 0.07 156.765 ;
    END
  END rw0_rd_out[109]
  PIN rw0_rd_out[110]
    DIRECTION OUTPUT ;
    USE SIGNAL ;
    SHAPE ABUTMENT ;
    PORT
      LAYER M3 ;
      RECT 0 157.115 0.07 157.185 ;
    END
  END rw0_rd_out[110]
  PIN rw0_rd_out[111]
    DIRECTION OUTPUT ;
    USE SIGNAL ;
    SHAPE ABUTMENT ;
    PORT
      LAYER M3 ;
      RECT 0 157.535 0.07 157.605 ;
    END
  END rw0_rd_out[111]
  PIN rw0_rd_out[112]
    DIRECTION OUTPUT ;
    USE SIGNAL ;
    SHAPE ABUTMENT ;
    PORT
      LAYER M3 ;
      RECT 0 157.955 0.07 158.025 ;
    END
  END rw0_rd_out[112]
  PIN rw0_rd_out[113]
    DIRECTION OUTPUT ;
    USE SIGNAL ;
    SHAPE ABUTMENT ;
    PORT
      LAYER M3 ;
      RECT 0 158.375 0.07 158.445 ;
    END
  END rw0_rd_out[113]
  PIN rw0_rd_out[114]
    DIRECTION OUTPUT ;
    USE SIGNAL ;
    SHAPE ABUTMENT ;
    PORT
      LAYER M3 ;
      RECT 0 158.795 0.07 158.865 ;
    END
  END rw0_rd_out[114]
  PIN rw0_rd_out[115]
    DIRECTION OUTPUT ;
    USE SIGNAL ;
    SHAPE ABUTMENT ;
    PORT
      LAYER M3 ;
      RECT 0 159.215 0.07 159.285 ;
    END
  END rw0_rd_out[115]
  PIN rw0_rd_out[116]
    DIRECTION OUTPUT ;
    USE SIGNAL ;
    SHAPE ABUTMENT ;
    PORT
      LAYER M3 ;
      RECT 0 159.635 0.07 159.705 ;
    END
  END rw0_rd_out[116]
  PIN rw0_rd_out[117]
    DIRECTION OUTPUT ;
    USE SIGNAL ;
    SHAPE ABUTMENT ;
    PORT
      LAYER M3 ;
      RECT 0 160.055 0.07 160.125 ;
    END
  END rw0_rd_out[117]
  PIN rw0_rd_out[118]
    DIRECTION OUTPUT ;
    USE SIGNAL ;
    SHAPE ABUTMENT ;
    PORT
      LAYER M3 ;
      RECT 0 160.475 0.07 160.545 ;
    END
  END rw0_rd_out[118]
  PIN rw0_rd_out[119]
    DIRECTION OUTPUT ;
    USE SIGNAL ;
    SHAPE ABUTMENT ;
    PORT
      LAYER M3 ;
      RECT 0 160.895 0.07 160.965 ;
    END
  END rw0_rd_out[119]
  PIN rw0_rd_out[120]
    DIRECTION OUTPUT ;
    USE SIGNAL ;
    SHAPE ABUTMENT ;
    PORT
      LAYER M3 ;
      RECT 0 161.315 0.07 161.385 ;
    END
  END rw0_rd_out[120]
  PIN rw0_rd_out[121]
    DIRECTION OUTPUT ;
    USE SIGNAL ;
    SHAPE ABUTMENT ;
    PORT
      LAYER M3 ;
      RECT 0 161.735 0.07 161.805 ;
    END
  END rw0_rd_out[121]
  PIN rw0_rd_out[122]
    DIRECTION OUTPUT ;
    USE SIGNAL ;
    SHAPE ABUTMENT ;
    PORT
      LAYER M3 ;
      RECT 0 162.155 0.07 162.225 ;
    END
  END rw0_rd_out[122]
  PIN rw0_rd_out[123]
    DIRECTION OUTPUT ;
    USE SIGNAL ;
    SHAPE ABUTMENT ;
    PORT
      LAYER M3 ;
      RECT 0 162.575 0.07 162.645 ;
    END
  END rw0_rd_out[123]
  PIN rw0_rd_out[124]
    DIRECTION OUTPUT ;
    USE SIGNAL ;
    SHAPE ABUTMENT ;
    PORT
      LAYER M3 ;
      RECT 0 162.995 0.07 163.065 ;
    END
  END rw0_rd_out[124]
  PIN rw0_rd_out[125]
    DIRECTION OUTPUT ;
    USE SIGNAL ;
    SHAPE ABUTMENT ;
    PORT
      LAYER M3 ;
      RECT 0 163.415 0.07 163.485 ;
    END
  END rw0_rd_out[125]
  PIN rw0_rd_out[126]
    DIRECTION OUTPUT ;
    USE SIGNAL ;
    SHAPE ABUTMENT ;
    PORT
      LAYER M3 ;
      RECT 0 163.835 0.07 163.905 ;
    END
  END rw0_rd_out[126]
  PIN rw0_rd_out[127]
    DIRECTION OUTPUT ;
    USE SIGNAL ;
    SHAPE ABUTMENT ;
    PORT
      LAYER M3 ;
      RECT 0 164.255 0.07 164.325 ;
    END
  END rw0_rd_out[127]
  PIN rw0_rd_out[128]
    DIRECTION OUTPUT ;
    USE SIGNAL ;
    SHAPE ABUTMENT ;
    PORT
      LAYER M3 ;
      RECT 0 164.675 0.07 164.745 ;
    END
  END rw0_rd_out[128]
  PIN rw0_rd_out[129]
    DIRECTION OUTPUT ;
    USE SIGNAL ;
    SHAPE ABUTMENT ;
    PORT
      LAYER M3 ;
      RECT 0 165.095 0.07 165.165 ;
    END
  END rw0_rd_out[129]
  PIN rw0_rd_out[130]
    DIRECTION OUTPUT ;
    USE SIGNAL ;
    SHAPE ABUTMENT ;
    PORT
      LAYER M3 ;
      RECT 0 165.515 0.07 165.585 ;
    END
  END rw0_rd_out[130]
  PIN rw0_rd_out[131]
    DIRECTION OUTPUT ;
    USE SIGNAL ;
    SHAPE ABUTMENT ;
    PORT
      LAYER M3 ;
      RECT 0 165.935 0.07 166.005 ;
    END
  END rw0_rd_out[131]
  PIN rw0_rd_out[132]
    DIRECTION OUTPUT ;
    USE SIGNAL ;
    SHAPE ABUTMENT ;
    PORT
      LAYER M3 ;
      RECT 0 166.355 0.07 166.425 ;
    END
  END rw0_rd_out[132]
  PIN rw0_rd_out[133]
    DIRECTION OUTPUT ;
    USE SIGNAL ;
    SHAPE ABUTMENT ;
    PORT
      LAYER M3 ;
      RECT 0 166.775 0.07 166.845 ;
    END
  END rw0_rd_out[133]
  PIN rw0_rd_out[134]
    DIRECTION OUTPUT ;
    USE SIGNAL ;
    SHAPE ABUTMENT ;
    PORT
      LAYER M3 ;
      RECT 0 167.195 0.07 167.265 ;
    END
  END rw0_rd_out[134]
  PIN rw0_rd_out[135]
    DIRECTION OUTPUT ;
    USE SIGNAL ;
    SHAPE ABUTMENT ;
    PORT
      LAYER M3 ;
      RECT 0 167.615 0.07 167.685 ;
    END
  END rw0_rd_out[135]
  PIN rw0_rd_out[136]
    DIRECTION OUTPUT ;
    USE SIGNAL ;
    SHAPE ABUTMENT ;
    PORT
      LAYER M3 ;
      RECT 0 168.035 0.07 168.105 ;
    END
  END rw0_rd_out[136]
  PIN rw0_rd_out[137]
    DIRECTION OUTPUT ;
    USE SIGNAL ;
    SHAPE ABUTMENT ;
    PORT
      LAYER M3 ;
      RECT 0 168.455 0.07 168.525 ;
    END
  END rw0_rd_out[137]
  PIN rw0_rd_out[138]
    DIRECTION OUTPUT ;
    USE SIGNAL ;
    SHAPE ABUTMENT ;
    PORT
      LAYER M3 ;
      RECT 0 168.875 0.07 168.945 ;
    END
  END rw0_rd_out[138]
  PIN rw0_rd_out[139]
    DIRECTION OUTPUT ;
    USE SIGNAL ;
    SHAPE ABUTMENT ;
    PORT
      LAYER M3 ;
      RECT 0 169.295 0.07 169.365 ;
    END
  END rw0_rd_out[139]
  PIN rw0_rd_out[140]
    DIRECTION OUTPUT ;
    USE SIGNAL ;
    SHAPE ABUTMENT ;
    PORT
      LAYER M3 ;
      RECT 0 169.715 0.07 169.785 ;
    END
  END rw0_rd_out[140]
  PIN rw0_rd_out[141]
    DIRECTION OUTPUT ;
    USE SIGNAL ;
    SHAPE ABUTMENT ;
    PORT
      LAYER M3 ;
      RECT 0 170.135 0.07 170.205 ;
    END
  END rw0_rd_out[141]
  PIN rw0_rd_out[142]
    DIRECTION OUTPUT ;
    USE SIGNAL ;
    SHAPE ABUTMENT ;
    PORT
      LAYER M3 ;
      RECT 0 170.555 0.07 170.625 ;
    END
  END rw0_rd_out[142]
  PIN rw0_rd_out[143]
    DIRECTION OUTPUT ;
    USE SIGNAL ;
    SHAPE ABUTMENT ;
    PORT
      LAYER M3 ;
      RECT 0 170.975 0.07 171.045 ;
    END
  END rw0_rd_out[143]
  PIN rw0_rd_out[144]
    DIRECTION OUTPUT ;
    USE SIGNAL ;
    SHAPE ABUTMENT ;
    PORT
      LAYER M3 ;
      RECT 0 171.395 0.07 171.465 ;
    END
  END rw0_rd_out[144]
  PIN rw0_rd_out[145]
    DIRECTION OUTPUT ;
    USE SIGNAL ;
    SHAPE ABUTMENT ;
    PORT
      LAYER M3 ;
      RECT 0 171.815 0.07 171.885 ;
    END
  END rw0_rd_out[145]
  PIN rw0_rd_out[146]
    DIRECTION OUTPUT ;
    USE SIGNAL ;
    SHAPE ABUTMENT ;
    PORT
      LAYER M3 ;
      RECT 0 172.235 0.07 172.305 ;
    END
  END rw0_rd_out[146]
  PIN rw0_rd_out[147]
    DIRECTION OUTPUT ;
    USE SIGNAL ;
    SHAPE ABUTMENT ;
    PORT
      LAYER M3 ;
      RECT 0 172.655 0.07 172.725 ;
    END
  END rw0_rd_out[147]
  PIN rw0_rd_out[148]
    DIRECTION OUTPUT ;
    USE SIGNAL ;
    SHAPE ABUTMENT ;
    PORT
      LAYER M3 ;
      RECT 0 173.075 0.07 173.145 ;
    END
  END rw0_rd_out[148]
  PIN rw0_rd_out[149]
    DIRECTION OUTPUT ;
    USE SIGNAL ;
    SHAPE ABUTMENT ;
    PORT
      LAYER M3 ;
      RECT 0 173.495 0.07 173.565 ;
    END
  END rw0_rd_out[149]
  PIN rw0_rd_out[150]
    DIRECTION OUTPUT ;
    USE SIGNAL ;
    SHAPE ABUTMENT ;
    PORT
      LAYER M3 ;
      RECT 0 173.915 0.07 173.985 ;
    END
  END rw0_rd_out[150]
  PIN rw0_rd_out[151]
    DIRECTION OUTPUT ;
    USE SIGNAL ;
    SHAPE ABUTMENT ;
    PORT
      LAYER M3 ;
      RECT 0 174.335 0.07 174.405 ;
    END
  END rw0_rd_out[151]
  PIN rw0_rd_out[152]
    DIRECTION OUTPUT ;
    USE SIGNAL ;
    SHAPE ABUTMENT ;
    PORT
      LAYER M3 ;
      RECT 0 174.755 0.07 174.825 ;
    END
  END rw0_rd_out[152]
  PIN rw0_rd_out[153]
    DIRECTION OUTPUT ;
    USE SIGNAL ;
    SHAPE ABUTMENT ;
    PORT
      LAYER M3 ;
      RECT 0 175.175 0.07 175.245 ;
    END
  END rw0_rd_out[153]
  PIN rw0_rd_out[154]
    DIRECTION OUTPUT ;
    USE SIGNAL ;
    SHAPE ABUTMENT ;
    PORT
      LAYER M3 ;
      RECT 0 175.595 0.07 175.665 ;
    END
  END rw0_rd_out[154]
  PIN rw0_rd_out[155]
    DIRECTION OUTPUT ;
    USE SIGNAL ;
    SHAPE ABUTMENT ;
    PORT
      LAYER M3 ;
      RECT 0 176.015 0.07 176.085 ;
    END
  END rw0_rd_out[155]
  PIN rw0_rd_out[156]
    DIRECTION OUTPUT ;
    USE SIGNAL ;
    SHAPE ABUTMENT ;
    PORT
      LAYER M3 ;
      RECT 0 176.435 0.07 176.505 ;
    END
  END rw0_rd_out[156]
  PIN rw0_rd_out[157]
    DIRECTION OUTPUT ;
    USE SIGNAL ;
    SHAPE ABUTMENT ;
    PORT
      LAYER M3 ;
      RECT 0 176.855 0.07 176.925 ;
    END
  END rw0_rd_out[157]
  PIN rw0_rd_out[158]
    DIRECTION OUTPUT ;
    USE SIGNAL ;
    SHAPE ABUTMENT ;
    PORT
      LAYER M3 ;
      RECT 0 177.275 0.07 177.345 ;
    END
  END rw0_rd_out[158]
  PIN rw0_rd_out[159]
    DIRECTION OUTPUT ;
    USE SIGNAL ;
    SHAPE ABUTMENT ;
    PORT
      LAYER M3 ;
      RECT 0 177.695 0.07 177.765 ;
    END
  END rw0_rd_out[159]
  PIN rw0_rd_out[160]
    DIRECTION OUTPUT ;
    USE SIGNAL ;
    SHAPE ABUTMENT ;
    PORT
      LAYER M3 ;
      RECT 0 178.115 0.07 178.185 ;
    END
  END rw0_rd_out[160]
  PIN rw0_rd_out[161]
    DIRECTION OUTPUT ;
    USE SIGNAL ;
    SHAPE ABUTMENT ;
    PORT
      LAYER M3 ;
      RECT 0 178.535 0.07 178.605 ;
    END
  END rw0_rd_out[161]
  PIN rw0_rd_out[162]
    DIRECTION OUTPUT ;
    USE SIGNAL ;
    SHAPE ABUTMENT ;
    PORT
      LAYER M3 ;
      RECT 0 178.955 0.07 179.025 ;
    END
  END rw0_rd_out[162]
  PIN rw0_rd_out[163]
    DIRECTION OUTPUT ;
    USE SIGNAL ;
    SHAPE ABUTMENT ;
    PORT
      LAYER M3 ;
      RECT 0 179.375 0.07 179.445 ;
    END
  END rw0_rd_out[163]
  PIN rw0_rd_out[164]
    DIRECTION OUTPUT ;
    USE SIGNAL ;
    SHAPE ABUTMENT ;
    PORT
      LAYER M3 ;
      RECT 0 179.795 0.07 179.865 ;
    END
  END rw0_rd_out[164]
  PIN rw0_rd_out[165]
    DIRECTION OUTPUT ;
    USE SIGNAL ;
    SHAPE ABUTMENT ;
    PORT
      LAYER M3 ;
      RECT 0 180.215 0.07 180.285 ;
    END
  END rw0_rd_out[165]
  PIN rw0_rd_out[166]
    DIRECTION OUTPUT ;
    USE SIGNAL ;
    SHAPE ABUTMENT ;
    PORT
      LAYER M3 ;
      RECT 0 180.635 0.07 180.705 ;
    END
  END rw0_rd_out[166]
  PIN rw0_rd_out[167]
    DIRECTION OUTPUT ;
    USE SIGNAL ;
    SHAPE ABUTMENT ;
    PORT
      LAYER M3 ;
      RECT 0 181.055 0.07 181.125 ;
    END
  END rw0_rd_out[167]
  PIN rw0_rd_out[168]
    DIRECTION OUTPUT ;
    USE SIGNAL ;
    SHAPE ABUTMENT ;
    PORT
      LAYER M3 ;
      RECT 0 181.475 0.07 181.545 ;
    END
  END rw0_rd_out[168]
  PIN rw0_rd_out[169]
    DIRECTION OUTPUT ;
    USE SIGNAL ;
    SHAPE ABUTMENT ;
    PORT
      LAYER M3 ;
      RECT 0 181.895 0.07 181.965 ;
    END
  END rw0_rd_out[169]
  PIN rw0_rd_out[170]
    DIRECTION OUTPUT ;
    USE SIGNAL ;
    SHAPE ABUTMENT ;
    PORT
      LAYER M3 ;
      RECT 0 182.315 0.07 182.385 ;
    END
  END rw0_rd_out[170]
  PIN rw0_rd_out[171]
    DIRECTION OUTPUT ;
    USE SIGNAL ;
    SHAPE ABUTMENT ;
    PORT
      LAYER M3 ;
      RECT 0 182.735 0.07 182.805 ;
    END
  END rw0_rd_out[171]
  PIN rw0_rd_out[172]
    DIRECTION OUTPUT ;
    USE SIGNAL ;
    SHAPE ABUTMENT ;
    PORT
      LAYER M3 ;
      RECT 0 183.155 0.07 183.225 ;
    END
  END rw0_rd_out[172]
  PIN rw0_rd_out[173]
    DIRECTION OUTPUT ;
    USE SIGNAL ;
    SHAPE ABUTMENT ;
    PORT
      LAYER M3 ;
      RECT 0 183.575 0.07 183.645 ;
    END
  END rw0_rd_out[173]
  PIN rw0_rd_out[174]
    DIRECTION OUTPUT ;
    USE SIGNAL ;
    SHAPE ABUTMENT ;
    PORT
      LAYER M3 ;
      RECT 0 183.995 0.07 184.065 ;
    END
  END rw0_rd_out[174]
  PIN rw0_rd_out[175]
    DIRECTION OUTPUT ;
    USE SIGNAL ;
    SHAPE ABUTMENT ;
    PORT
      LAYER M3 ;
      RECT 0 184.415 0.07 184.485 ;
    END
  END rw0_rd_out[175]
  PIN rw0_rd_out[176]
    DIRECTION OUTPUT ;
    USE SIGNAL ;
    SHAPE ABUTMENT ;
    PORT
      LAYER M3 ;
      RECT 0 184.835 0.07 184.905 ;
    END
  END rw0_rd_out[176]
  PIN rw0_rd_out[177]
    DIRECTION OUTPUT ;
    USE SIGNAL ;
    SHAPE ABUTMENT ;
    PORT
      LAYER M3 ;
      RECT 0 185.255 0.07 185.325 ;
    END
  END rw0_rd_out[177]
  PIN rw0_rd_out[178]
    DIRECTION OUTPUT ;
    USE SIGNAL ;
    SHAPE ABUTMENT ;
    PORT
      LAYER M3 ;
      RECT 0 185.675 0.07 185.745 ;
    END
  END rw0_rd_out[178]
  PIN rw0_rd_out[179]
    DIRECTION OUTPUT ;
    USE SIGNAL ;
    SHAPE ABUTMENT ;
    PORT
      LAYER M3 ;
      RECT 0 186.095 0.07 186.165 ;
    END
  END rw0_rd_out[179]
  PIN rw0_rd_out[180]
    DIRECTION OUTPUT ;
    USE SIGNAL ;
    SHAPE ABUTMENT ;
    PORT
      LAYER M3 ;
      RECT 0 186.515 0.07 186.585 ;
    END
  END rw0_rd_out[180]
  PIN rw0_rd_out[181]
    DIRECTION OUTPUT ;
    USE SIGNAL ;
    SHAPE ABUTMENT ;
    PORT
      LAYER M3 ;
      RECT 0 186.935 0.07 187.005 ;
    END
  END rw0_rd_out[181]
  PIN rw0_rd_out[182]
    DIRECTION OUTPUT ;
    USE SIGNAL ;
    SHAPE ABUTMENT ;
    PORT
      LAYER M3 ;
      RECT 0 187.355 0.07 187.425 ;
    END
  END rw0_rd_out[182]
  PIN rw0_rd_out[183]
    DIRECTION OUTPUT ;
    USE SIGNAL ;
    SHAPE ABUTMENT ;
    PORT
      LAYER M3 ;
      RECT 0 187.775 0.07 187.845 ;
    END
  END rw0_rd_out[183]
  PIN rw0_rd_out[184]
    DIRECTION OUTPUT ;
    USE SIGNAL ;
    SHAPE ABUTMENT ;
    PORT
      LAYER M3 ;
      RECT 0 188.195 0.07 188.265 ;
    END
  END rw0_rd_out[184]
  PIN rw0_rd_out[185]
    DIRECTION OUTPUT ;
    USE SIGNAL ;
    SHAPE ABUTMENT ;
    PORT
      LAYER M3 ;
      RECT 0 188.615 0.07 188.685 ;
    END
  END rw0_rd_out[185]
  PIN rw0_rd_out[186]
    DIRECTION OUTPUT ;
    USE SIGNAL ;
    SHAPE ABUTMENT ;
    PORT
      LAYER M3 ;
      RECT 0 189.035 0.07 189.105 ;
    END
  END rw0_rd_out[186]
  PIN rw0_rd_out[187]
    DIRECTION OUTPUT ;
    USE SIGNAL ;
    SHAPE ABUTMENT ;
    PORT
      LAYER M3 ;
      RECT 0 189.455 0.07 189.525 ;
    END
  END rw0_rd_out[187]
  PIN rw0_rd_out[188]
    DIRECTION OUTPUT ;
    USE SIGNAL ;
    SHAPE ABUTMENT ;
    PORT
      LAYER M3 ;
      RECT 0 189.875 0.07 189.945 ;
    END
  END rw0_rd_out[188]
  PIN rw0_rd_out[189]
    DIRECTION OUTPUT ;
    USE SIGNAL ;
    SHAPE ABUTMENT ;
    PORT
      LAYER M3 ;
      RECT 0 190.295 0.07 190.365 ;
    END
  END rw0_rd_out[189]
  PIN rw0_rd_out[190]
    DIRECTION OUTPUT ;
    USE SIGNAL ;
    SHAPE ABUTMENT ;
    PORT
      LAYER M3 ;
      RECT 0 190.715 0.07 190.785 ;
    END
  END rw0_rd_out[190]
  PIN rw0_rd_out[191]
    DIRECTION OUTPUT ;
    USE SIGNAL ;
    SHAPE ABUTMENT ;
    PORT
      LAYER M3 ;
      RECT 0 191.135 0.07 191.205 ;
    END
  END rw0_rd_out[191]
  PIN rw0_rd_out[192]
    DIRECTION OUTPUT ;
    USE SIGNAL ;
    SHAPE ABUTMENT ;
    PORT
      LAYER M3 ;
      RECT 0 191.555 0.07 191.625 ;
    END
  END rw0_rd_out[192]
  PIN rw0_rd_out[193]
    DIRECTION OUTPUT ;
    USE SIGNAL ;
    SHAPE ABUTMENT ;
    PORT
      LAYER M3 ;
      RECT 0 191.975 0.07 192.045 ;
    END
  END rw0_rd_out[193]
  PIN rw0_rd_out[194]
    DIRECTION OUTPUT ;
    USE SIGNAL ;
    SHAPE ABUTMENT ;
    PORT
      LAYER M3 ;
      RECT 0 192.395 0.07 192.465 ;
    END
  END rw0_rd_out[194]
  PIN rw0_rd_out[195]
    DIRECTION OUTPUT ;
    USE SIGNAL ;
    SHAPE ABUTMENT ;
    PORT
      LAYER M3 ;
      RECT 0 192.815 0.07 192.885 ;
    END
  END rw0_rd_out[195]
  PIN rw0_rd_out[196]
    DIRECTION OUTPUT ;
    USE SIGNAL ;
    SHAPE ABUTMENT ;
    PORT
      LAYER M3 ;
      RECT 0 193.235 0.07 193.305 ;
    END
  END rw0_rd_out[196]
  PIN rw0_rd_out[197]
    DIRECTION OUTPUT ;
    USE SIGNAL ;
    SHAPE ABUTMENT ;
    PORT
      LAYER M3 ;
      RECT 0 193.655 0.07 193.725 ;
    END
  END rw0_rd_out[197]
  PIN rw0_rd_out[198]
    DIRECTION OUTPUT ;
    USE SIGNAL ;
    SHAPE ABUTMENT ;
    PORT
      LAYER M3 ;
      RECT 0 194.075 0.07 194.145 ;
    END
  END rw0_rd_out[198]
  PIN rw0_rd_out[199]
    DIRECTION OUTPUT ;
    USE SIGNAL ;
    SHAPE ABUTMENT ;
    PORT
      LAYER M3 ;
      RECT 0 194.495 0.07 194.565 ;
    END
  END rw0_rd_out[199]
  PIN rw0_rd_out[200]
    DIRECTION OUTPUT ;
    USE SIGNAL ;
    SHAPE ABUTMENT ;
    PORT
      LAYER M3 ;
      RECT 0 194.915 0.07 194.985 ;
    END
  END rw0_rd_out[200]
  PIN rw0_rd_out[201]
    DIRECTION OUTPUT ;
    USE SIGNAL ;
    SHAPE ABUTMENT ;
    PORT
      LAYER M3 ;
      RECT 0 195.335 0.07 195.405 ;
    END
  END rw0_rd_out[201]
  PIN rw0_rd_out[202]
    DIRECTION OUTPUT ;
    USE SIGNAL ;
    SHAPE ABUTMENT ;
    PORT
      LAYER M3 ;
      RECT 0 195.755 0.07 195.825 ;
    END
  END rw0_rd_out[202]
  PIN rw0_rd_out[203]
    DIRECTION OUTPUT ;
    USE SIGNAL ;
    SHAPE ABUTMENT ;
    PORT
      LAYER M3 ;
      RECT 0 196.175 0.07 196.245 ;
    END
  END rw0_rd_out[203]
  PIN rw0_rd_out[204]
    DIRECTION OUTPUT ;
    USE SIGNAL ;
    SHAPE ABUTMENT ;
    PORT
      LAYER M3 ;
      RECT 0 196.595 0.07 196.665 ;
    END
  END rw0_rd_out[204]
  PIN rw0_rd_out[205]
    DIRECTION OUTPUT ;
    USE SIGNAL ;
    SHAPE ABUTMENT ;
    PORT
      LAYER M3 ;
      RECT 0 197.015 0.07 197.085 ;
    END
  END rw0_rd_out[205]
  PIN rw0_rd_out[206]
    DIRECTION OUTPUT ;
    USE SIGNAL ;
    SHAPE ABUTMENT ;
    PORT
      LAYER M3 ;
      RECT 0 197.435 0.07 197.505 ;
    END
  END rw0_rd_out[206]
  PIN rw0_rd_out[207]
    DIRECTION OUTPUT ;
    USE SIGNAL ;
    SHAPE ABUTMENT ;
    PORT
      LAYER M3 ;
      RECT 0 197.855 0.07 197.925 ;
    END
  END rw0_rd_out[207]
  PIN rw0_rd_out[208]
    DIRECTION OUTPUT ;
    USE SIGNAL ;
    SHAPE ABUTMENT ;
    PORT
      LAYER M3 ;
      RECT 0 198.275 0.07 198.345 ;
    END
  END rw0_rd_out[208]
  PIN rw0_rd_out[209]
    DIRECTION OUTPUT ;
    USE SIGNAL ;
    SHAPE ABUTMENT ;
    PORT
      LAYER M3 ;
      RECT 0 198.695 0.07 198.765 ;
    END
  END rw0_rd_out[209]
  PIN rw0_rd_out[210]
    DIRECTION OUTPUT ;
    USE SIGNAL ;
    SHAPE ABUTMENT ;
    PORT
      LAYER M3 ;
      RECT 0 199.115 0.07 199.185 ;
    END
  END rw0_rd_out[210]
  PIN rw0_rd_out[211]
    DIRECTION OUTPUT ;
    USE SIGNAL ;
    SHAPE ABUTMENT ;
    PORT
      LAYER M3 ;
      RECT 0 199.535 0.07 199.605 ;
    END
  END rw0_rd_out[211]
  PIN rw0_rd_out[212]
    DIRECTION OUTPUT ;
    USE SIGNAL ;
    SHAPE ABUTMENT ;
    PORT
      LAYER M3 ;
      RECT 0 199.955 0.07 200.025 ;
    END
  END rw0_rd_out[212]
  PIN rw0_rd_out[213]
    DIRECTION OUTPUT ;
    USE SIGNAL ;
    SHAPE ABUTMENT ;
    PORT
      LAYER M3 ;
      RECT 0 200.375 0.07 200.445 ;
    END
  END rw0_rd_out[213]
  PIN rw0_rd_out[214]
    DIRECTION OUTPUT ;
    USE SIGNAL ;
    SHAPE ABUTMENT ;
    PORT
      LAYER M3 ;
      RECT 0 200.795 0.07 200.865 ;
    END
  END rw0_rd_out[214]
  PIN rw0_rd_out[215]
    DIRECTION OUTPUT ;
    USE SIGNAL ;
    SHAPE ABUTMENT ;
    PORT
      LAYER M3 ;
      RECT 0 201.215 0.07 201.285 ;
    END
  END rw0_rd_out[215]
  PIN rw0_rd_out[216]
    DIRECTION OUTPUT ;
    USE SIGNAL ;
    SHAPE ABUTMENT ;
    PORT
      LAYER M3 ;
      RECT 0 201.635 0.07 201.705 ;
    END
  END rw0_rd_out[216]
  PIN rw0_rd_out[217]
    DIRECTION OUTPUT ;
    USE SIGNAL ;
    SHAPE ABUTMENT ;
    PORT
      LAYER M3 ;
      RECT 0 202.055 0.07 202.125 ;
    END
  END rw0_rd_out[217]
  PIN rw0_rd_out[218]
    DIRECTION OUTPUT ;
    USE SIGNAL ;
    SHAPE ABUTMENT ;
    PORT
      LAYER M3 ;
      RECT 0 202.475 0.07 202.545 ;
    END
  END rw0_rd_out[218]
  PIN rw0_rd_out[219]
    DIRECTION OUTPUT ;
    USE SIGNAL ;
    SHAPE ABUTMENT ;
    PORT
      LAYER M3 ;
      RECT 0 202.895 0.07 202.965 ;
    END
  END rw0_rd_out[219]
  PIN rw0_rd_out[220]
    DIRECTION OUTPUT ;
    USE SIGNAL ;
    SHAPE ABUTMENT ;
    PORT
      LAYER M3 ;
      RECT 0 203.315 0.07 203.385 ;
    END
  END rw0_rd_out[220]
  PIN rw0_rd_out[221]
    DIRECTION OUTPUT ;
    USE SIGNAL ;
    SHAPE ABUTMENT ;
    PORT
      LAYER M3 ;
      RECT 0 203.735 0.07 203.805 ;
    END
  END rw0_rd_out[221]
  PIN rw0_rd_out[222]
    DIRECTION OUTPUT ;
    USE SIGNAL ;
    SHAPE ABUTMENT ;
    PORT
      LAYER M3 ;
      RECT 0 204.155 0.07 204.225 ;
    END
  END rw0_rd_out[222]
  PIN rw0_rd_out[223]
    DIRECTION OUTPUT ;
    USE SIGNAL ;
    SHAPE ABUTMENT ;
    PORT
      LAYER M3 ;
      RECT 0 204.575 0.07 204.645 ;
    END
  END rw0_rd_out[223]
  PIN rw0_rd_out[224]
    DIRECTION OUTPUT ;
    USE SIGNAL ;
    SHAPE ABUTMENT ;
    PORT
      LAYER M3 ;
      RECT 0 204.995 0.07 205.065 ;
    END
  END rw0_rd_out[224]
  PIN rw0_rd_out[225]
    DIRECTION OUTPUT ;
    USE SIGNAL ;
    SHAPE ABUTMENT ;
    PORT
      LAYER M3 ;
      RECT 0 205.415 0.07 205.485 ;
    END
  END rw0_rd_out[225]
  PIN rw0_rd_out[226]
    DIRECTION OUTPUT ;
    USE SIGNAL ;
    SHAPE ABUTMENT ;
    PORT
      LAYER M3 ;
      RECT 0 205.835 0.07 205.905 ;
    END
  END rw0_rd_out[226]
  PIN rw0_rd_out[227]
    DIRECTION OUTPUT ;
    USE SIGNAL ;
    SHAPE ABUTMENT ;
    PORT
      LAYER M3 ;
      RECT 0 206.255 0.07 206.325 ;
    END
  END rw0_rd_out[227]
  PIN rw0_rd_out[228]
    DIRECTION OUTPUT ;
    USE SIGNAL ;
    SHAPE ABUTMENT ;
    PORT
      LAYER M3 ;
      RECT 0 206.675 0.07 206.745 ;
    END
  END rw0_rd_out[228]
  PIN rw0_rd_out[229]
    DIRECTION OUTPUT ;
    USE SIGNAL ;
    SHAPE ABUTMENT ;
    PORT
      LAYER M3 ;
      RECT 0 207.095 0.07 207.165 ;
    END
  END rw0_rd_out[229]
  PIN rw0_rd_out[230]
    DIRECTION OUTPUT ;
    USE SIGNAL ;
    SHAPE ABUTMENT ;
    PORT
      LAYER M3 ;
      RECT 0 207.515 0.07 207.585 ;
    END
  END rw0_rd_out[230]
  PIN rw0_rd_out[231]
    DIRECTION OUTPUT ;
    USE SIGNAL ;
    SHAPE ABUTMENT ;
    PORT
      LAYER M3 ;
      RECT 0 207.935 0.07 208.005 ;
    END
  END rw0_rd_out[231]
  PIN rw0_rd_out[232]
    DIRECTION OUTPUT ;
    USE SIGNAL ;
    SHAPE ABUTMENT ;
    PORT
      LAYER M3 ;
      RECT 0 208.355 0.07 208.425 ;
    END
  END rw0_rd_out[232]
  PIN rw0_rd_out[233]
    DIRECTION OUTPUT ;
    USE SIGNAL ;
    SHAPE ABUTMENT ;
    PORT
      LAYER M3 ;
      RECT 0 208.775 0.07 208.845 ;
    END
  END rw0_rd_out[233]
  PIN rw0_rd_out[234]
    DIRECTION OUTPUT ;
    USE SIGNAL ;
    SHAPE ABUTMENT ;
    PORT
      LAYER M3 ;
      RECT 0 209.195 0.07 209.265 ;
    END
  END rw0_rd_out[234]
  PIN rw0_rd_out[235]
    DIRECTION OUTPUT ;
    USE SIGNAL ;
    SHAPE ABUTMENT ;
    PORT
      LAYER M3 ;
      RECT 0 209.615 0.07 209.685 ;
    END
  END rw0_rd_out[235]
  PIN rw0_rd_out[236]
    DIRECTION OUTPUT ;
    USE SIGNAL ;
    SHAPE ABUTMENT ;
    PORT
      LAYER M3 ;
      RECT 0 210.035 0.07 210.105 ;
    END
  END rw0_rd_out[236]
  PIN rw0_rd_out[237]
    DIRECTION OUTPUT ;
    USE SIGNAL ;
    SHAPE ABUTMENT ;
    PORT
      LAYER M3 ;
      RECT 0 210.455 0.07 210.525 ;
    END
  END rw0_rd_out[237]
  PIN rw0_rd_out[238]
    DIRECTION OUTPUT ;
    USE SIGNAL ;
    SHAPE ABUTMENT ;
    PORT
      LAYER M3 ;
      RECT 0 210.875 0.07 210.945 ;
    END
  END rw0_rd_out[238]
  PIN rw0_rd_out[239]
    DIRECTION OUTPUT ;
    USE SIGNAL ;
    SHAPE ABUTMENT ;
    PORT
      LAYER M3 ;
      RECT 0 211.295 0.07 211.365 ;
    END
  END rw0_rd_out[239]
  PIN rw0_rd_out[240]
    DIRECTION OUTPUT ;
    USE SIGNAL ;
    SHAPE ABUTMENT ;
    PORT
      LAYER M3 ;
      RECT 0 211.715 0.07 211.785 ;
    END
  END rw0_rd_out[240]
  PIN rw0_rd_out[241]
    DIRECTION OUTPUT ;
    USE SIGNAL ;
    SHAPE ABUTMENT ;
    PORT
      LAYER M3 ;
      RECT 0 212.135 0.07 212.205 ;
    END
  END rw0_rd_out[241]
  PIN rw0_rd_out[242]
    DIRECTION OUTPUT ;
    USE SIGNAL ;
    SHAPE ABUTMENT ;
    PORT
      LAYER M3 ;
      RECT 0 212.555 0.07 212.625 ;
    END
  END rw0_rd_out[242]
  PIN rw0_rd_out[243]
    DIRECTION OUTPUT ;
    USE SIGNAL ;
    SHAPE ABUTMENT ;
    PORT
      LAYER M3 ;
      RECT 0 212.975 0.07 213.045 ;
    END
  END rw0_rd_out[243]
  PIN rw0_rd_out[244]
    DIRECTION OUTPUT ;
    USE SIGNAL ;
    SHAPE ABUTMENT ;
    PORT
      LAYER M3 ;
      RECT 0 213.395 0.07 213.465 ;
    END
  END rw0_rd_out[244]
  PIN rw0_rd_out[245]
    DIRECTION OUTPUT ;
    USE SIGNAL ;
    SHAPE ABUTMENT ;
    PORT
      LAYER M3 ;
      RECT 0 213.815 0.07 213.885 ;
    END
  END rw0_rd_out[245]
  PIN rw0_rd_out[246]
    DIRECTION OUTPUT ;
    USE SIGNAL ;
    SHAPE ABUTMENT ;
    PORT
      LAYER M3 ;
      RECT 0 214.235 0.07 214.305 ;
    END
  END rw0_rd_out[246]
  PIN rw0_rd_out[247]
    DIRECTION OUTPUT ;
    USE SIGNAL ;
    SHAPE ABUTMENT ;
    PORT
      LAYER M3 ;
      RECT 0 214.655 0.07 214.725 ;
    END
  END rw0_rd_out[247]
  PIN rw0_rd_out[248]
    DIRECTION OUTPUT ;
    USE SIGNAL ;
    SHAPE ABUTMENT ;
    PORT
      LAYER M3 ;
      RECT 0 215.075 0.07 215.145 ;
    END
  END rw0_rd_out[248]
  PIN rw0_rd_out[249]
    DIRECTION OUTPUT ;
    USE SIGNAL ;
    SHAPE ABUTMENT ;
    PORT
      LAYER M3 ;
      RECT 0 215.495 0.07 215.565 ;
    END
  END rw0_rd_out[249]
  PIN rw0_rd_out[250]
    DIRECTION OUTPUT ;
    USE SIGNAL ;
    SHAPE ABUTMENT ;
    PORT
      LAYER M3 ;
      RECT 0 215.915 0.07 215.985 ;
    END
  END rw0_rd_out[250]
  PIN rw0_rd_out[251]
    DIRECTION OUTPUT ;
    USE SIGNAL ;
    SHAPE ABUTMENT ;
    PORT
      LAYER M3 ;
      RECT 0 216.335 0.07 216.405 ;
    END
  END rw0_rd_out[251]
  PIN rw0_rd_out[252]
    DIRECTION OUTPUT ;
    USE SIGNAL ;
    SHAPE ABUTMENT ;
    PORT
      LAYER M3 ;
      RECT 0 216.755 0.07 216.825 ;
    END
  END rw0_rd_out[252]
  PIN rw0_rd_out[253]
    DIRECTION OUTPUT ;
    USE SIGNAL ;
    SHAPE ABUTMENT ;
    PORT
      LAYER M3 ;
      RECT 0 217.175 0.07 217.245 ;
    END
  END rw0_rd_out[253]
  PIN rw0_rd_out[254]
    DIRECTION OUTPUT ;
    USE SIGNAL ;
    SHAPE ABUTMENT ;
    PORT
      LAYER M3 ;
      RECT 0 217.595 0.07 217.665 ;
    END
  END rw0_rd_out[254]
  PIN rw0_rd_out[255]
    DIRECTION OUTPUT ;
    USE SIGNAL ;
    SHAPE ABUTMENT ;
    PORT
      LAYER M3 ;
      RECT 0 218.015 0.07 218.085 ;
    END
  END rw0_rd_out[255]
  PIN rw0_addr_in[0]
    DIRECTION INPUT ;
    USE SIGNAL ;
    SHAPE ABUTMENT ;
    PORT
      LAYER M3 ;
      RECT 0 218.435 0.07 218.505 ;
    END
  END rw0_addr_in[0]
  PIN rw0_addr_in[1]
    DIRECTION INPUT ;
    USE SIGNAL ;
    SHAPE ABUTMENT ;
    PORT
      LAYER M3 ;
      RECT 0 218.855 0.07 218.925 ;
    END
  END rw0_addr_in[1]
  PIN rw0_addr_in[2]
    DIRECTION INPUT ;
    USE SIGNAL ;
    SHAPE ABUTMENT ;
    PORT
      LAYER M3 ;
      RECT 0 219.275 0.07 219.345 ;
    END
  END rw0_addr_in[2]
  PIN rw0_addr_in[3]
    DIRECTION INPUT ;
    USE SIGNAL ;
    SHAPE ABUTMENT ;
    PORT
      LAYER M3 ;
      RECT 0 219.695 0.07 219.765 ;
    END
  END rw0_addr_in[3]
  PIN rw0_addr_in[4]
    DIRECTION INPUT ;
    USE SIGNAL ;
    SHAPE ABUTMENT ;
    PORT
      LAYER M3 ;
      RECT 0 220.115 0.07 220.185 ;
    END
  END rw0_addr_in[4]
  PIN rw0_addr_in[5]
    DIRECTION INPUT ;
    USE SIGNAL ;
    SHAPE ABUTMENT ;
    PORT
      LAYER M3 ;
      RECT 0 220.535 0.07 220.605 ;
    END
  END rw0_addr_in[5]
  PIN rw0_addr_in[6]
    DIRECTION INPUT ;
    USE SIGNAL ;
    SHAPE ABUTMENT ;
    PORT
      LAYER M3 ;
      RECT 0 220.955 0.07 221.025 ;
    END
  END rw0_addr_in[6]
  PIN rw0_addr_in[7]
    DIRECTION INPUT ;
    USE SIGNAL ;
    SHAPE ABUTMENT ;
    PORT
      LAYER M3 ;
      RECT 0 221.375 0.07 221.445 ;
    END
  END rw0_addr_in[7]
  PIN rw0_we_in
    DIRECTION INPUT ;
    USE SIGNAL ;
    SHAPE ABUTMENT ;
    PORT
      LAYER M3 ;
      RECT 0 221.795 0.07 221.865 ;
    END
  END rw0_we_in
  PIN rw0_ce_in
    DIRECTION INPUT ;
    USE SIGNAL ;
    SHAPE ABUTMENT ;
    PORT
      LAYER M3 ;
      RECT 0 222.215 0.07 222.285 ;
    END
  END rw0_ce_in
  PIN rw0_clk
    DIRECTION INPUT ;
    USE SIGNAL ;
    SHAPE ABUTMENT ;
    PORT
      LAYER M3 ;
      RECT 0 222.635 0.07 222.705 ;
    END
  END rw0_clk
  PIN VSS
    DIRECTION INOUT ;
    USE GROUND ;
    PORT
      LAYER M4 ;
      RECT 1 0.84 1.28 235.76 ;
      RECT 3.24 0.84 3.52 235.76 ;
      RECT 5.48 0.84 5.76 235.76 ;
      RECT 7.72 0.84 8 235.76 ;
      RECT 9.96 0.84 10.24 235.76 ;
      RECT 12.2 0.84 12.48 235.76 ;
      RECT 14.44 0.84 14.72 235.76 ;
      RECT 16.68 0.84 16.96 235.76 ;
      RECT 18.92 0.84 19.2 235.76 ;
      RECT 21.16 0.84 21.44 235.76 ;
      RECT 23.4 0.84 23.68 235.76 ;
      RECT 25.64 0.84 25.92 235.76 ;
      RECT 27.88 0.84 28.16 235.76 ;
      RECT 30.12 0.84 30.4 235.76 ;
      RECT 32.36 0.84 32.64 235.76 ;
      RECT 34.6 0.84 34.88 235.76 ;
      RECT 36.84 0.84 37.12 235.76 ;
      RECT 39.08 0.84 39.36 235.76 ;
      RECT 41.32 0.84 41.6 235.76 ;
      RECT 43.56 0.84 43.84 235.76 ;
      RECT 45.8 0.84 46.08 235.76 ;
      RECT 48.04 0.84 48.32 235.76 ;
      RECT 50.28 0.84 50.56 235.76 ;
      RECT 52.52 0.84 52.8 235.76 ;
      RECT 54.76 0.84 55.04 235.76 ;
      RECT 57 0.84 57.28 235.76 ;
      RECT 59.24 0.84 59.52 235.76 ;
      RECT 61.48 0.84 61.76 235.76 ;
      RECT 63.72 0.84 64 235.76 ;
      RECT 65.96 0.84 66.24 235.76 ;
      RECT 68.2 0.84 68.48 235.76 ;
      RECT 70.44 0.84 70.72 235.76 ;
      RECT 72.68 0.84 72.96 235.76 ;
      RECT 74.92 0.84 75.2 235.76 ;
      RECT 77.16 0.84 77.44 235.76 ;
      RECT 79.4 0.84 79.68 235.76 ;
      RECT 81.64 0.84 81.92 235.76 ;
      RECT 83.88 0.84 84.16 235.76 ;
      RECT 86.12 0.84 86.4 235.76 ;
      RECT 88.36 0.84 88.64 235.76 ;
      RECT 90.6 0.84 90.88 235.76 ;
      RECT 92.84 0.84 93.12 235.76 ;
      RECT 95.08 0.84 95.36 235.76 ;
      RECT 97.32 0.84 97.6 235.76 ;
      RECT 99.56 0.84 99.84 235.76 ;
      RECT 101.8 0.84 102.08 235.76 ;
      RECT 104.04 0.84 104.32 235.76 ;
      RECT 106.28 0.84 106.56 235.76 ;
      RECT 108.52 0.84 108.8 235.76 ;
      RECT 110.76 0.84 111.04 235.76 ;
      RECT 113 0.84 113.28 235.76 ;
      RECT 115.24 0.84 115.52 235.76 ;
      RECT 117.48 0.84 117.76 235.76 ;
      RECT 119.72 0.84 120 235.76 ;
      RECT 121.96 0.84 122.24 235.76 ;
      RECT 124.2 0.84 124.48 235.76 ;
      RECT 126.44 0.84 126.72 235.76 ;
      RECT 128.68 0.84 128.96 235.76 ;
      RECT 130.92 0.84 131.2 235.76 ;
      RECT 133.16 0.84 133.44 235.76 ;
      RECT 135.4 0.84 135.68 235.76 ;
      RECT 137.64 0.84 137.92 235.76 ;
      RECT 139.88 0.84 140.16 235.76 ;
      RECT 142.12 0.84 142.4 235.76 ;
      RECT 144.36 0.84 144.64 235.76 ;
      RECT 146.6 0.84 146.88 235.76 ;
      RECT 148.84 0.84 149.12 235.76 ;
      RECT 151.08 0.84 151.36 235.76 ;
      RECT 153.32 0.84 153.6 235.76 ;
      RECT 155.56 0.84 155.84 235.76 ;
      RECT 157.8 0.84 158.08 235.76 ;
      RECT 160.04 0.84 160.32 235.76 ;
      RECT 162.28 0.84 162.56 235.76 ;
      RECT 164.52 0.84 164.8 235.76 ;
      RECT 166.76 0.84 167.04 235.76 ;
      RECT 169 0.84 169.28 235.76 ;
      RECT 171.24 0.84 171.52 235.76 ;
      RECT 173.48 0.84 173.76 235.76 ;
      RECT 175.72 0.84 176 235.76 ;
      RECT 177.96 0.84 178.24 235.76 ;
      RECT 180.2 0.84 180.48 235.76 ;
      RECT 182.44 0.84 182.72 235.76 ;
      RECT 184.68 0.84 184.96 235.76 ;
      RECT 186.92 0.84 187.2 235.76 ;
      RECT 189.16 0.84 189.44 235.76 ;
      RECT 191.4 0.84 191.68 235.76 ;
      RECT 193.64 0.84 193.92 235.76 ;
      RECT 195.88 0.84 196.16 235.76 ;
      RECT 198.12 0.84 198.4 235.76 ;
      RECT 200.36 0.84 200.64 235.76 ;
      RECT 202.6 0.84 202.88 235.76 ;
      RECT 204.84 0.84 205.12 235.76 ;
      RECT 207.08 0.84 207.36 235.76 ;
      RECT 209.32 0.84 209.6 235.76 ;
      RECT 211.56 0.84 211.84 235.76 ;
      RECT 213.8 0.84 214.08 235.76 ;
      RECT 216.04 0.84 216.32 235.76 ;
      RECT 218.28 0.84 218.56 235.76 ;
      RECT 220.52 0.84 220.8 235.76 ;
      RECT 222.76 0.84 223.04 235.76 ;
      RECT 225 0.84 225.28 235.76 ;
      RECT 227.24 0.84 227.52 235.76 ;
      RECT 229.48 0.84 229.76 235.76 ;
      RECT 231.72 0.84 232 235.76 ;
      RECT 233.96 0.84 234.24 235.76 ;
      RECT 236.2 0.84 236.48 235.76 ;
    END
  END VSS
  PIN VDD
    DIRECTION INOUT ;
    USE POWER ;
    PORT
      LAYER M4 ;
      RECT 2.12 0.84 2.4 235.76 ;
      RECT 4.36 0.84 4.64 235.76 ;
      RECT 6.6 0.84 6.88 235.76 ;
      RECT 8.84 0.84 9.12 235.76 ;
      RECT 11.08 0.84 11.36 235.76 ;
      RECT 13.32 0.84 13.6 235.76 ;
      RECT 15.56 0.84 15.84 235.76 ;
      RECT 17.8 0.84 18.08 235.76 ;
      RECT 20.04 0.84 20.32 235.76 ;
      RECT 22.28 0.84 22.56 235.76 ;
      RECT 24.52 0.84 24.8 235.76 ;
      RECT 26.76 0.84 27.04 235.76 ;
      RECT 29 0.84 29.28 235.76 ;
      RECT 31.24 0.84 31.52 235.76 ;
      RECT 33.48 0.84 33.76 235.76 ;
      RECT 35.72 0.84 36 235.76 ;
      RECT 37.96 0.84 38.24 235.76 ;
      RECT 40.2 0.84 40.48 235.76 ;
      RECT 42.44 0.84 42.72 235.76 ;
      RECT 44.68 0.84 44.96 235.76 ;
      RECT 46.92 0.84 47.2 235.76 ;
      RECT 49.16 0.84 49.44 235.76 ;
      RECT 51.4 0.84 51.68 235.76 ;
      RECT 53.64 0.84 53.92 235.76 ;
      RECT 55.88 0.84 56.16 235.76 ;
      RECT 58.12 0.84 58.4 235.76 ;
      RECT 60.36 0.84 60.64 235.76 ;
      RECT 62.6 0.84 62.88 235.76 ;
      RECT 64.84 0.84 65.12 235.76 ;
      RECT 67.08 0.84 67.36 235.76 ;
      RECT 69.32 0.84 69.6 235.76 ;
      RECT 71.56 0.84 71.84 235.76 ;
      RECT 73.8 0.84 74.08 235.76 ;
      RECT 76.04 0.84 76.32 235.76 ;
      RECT 78.28 0.84 78.56 235.76 ;
      RECT 80.52 0.84 80.8 235.76 ;
      RECT 82.76 0.84 83.04 235.76 ;
      RECT 85 0.84 85.28 235.76 ;
      RECT 87.24 0.84 87.52 235.76 ;
      RECT 89.48 0.84 89.76 235.76 ;
      RECT 91.72 0.84 92 235.76 ;
      RECT 93.96 0.84 94.24 235.76 ;
      RECT 96.2 0.84 96.48 235.76 ;
      RECT 98.44 0.84 98.72 235.76 ;
      RECT 100.68 0.84 100.96 235.76 ;
      RECT 102.92 0.84 103.2 235.76 ;
      RECT 105.16 0.84 105.44 235.76 ;
      RECT 107.4 0.84 107.68 235.76 ;
      RECT 109.64 0.84 109.92 235.76 ;
      RECT 111.88 0.84 112.16 235.76 ;
      RECT 114.12 0.84 114.4 235.76 ;
      RECT 116.36 0.84 116.64 235.76 ;
      RECT 118.6 0.84 118.88 235.76 ;
      RECT 120.84 0.84 121.12 235.76 ;
      RECT 123.08 0.84 123.36 235.76 ;
      RECT 125.32 0.84 125.6 235.76 ;
      RECT 127.56 0.84 127.84 235.76 ;
      RECT 129.8 0.84 130.08 235.76 ;
      RECT 132.04 0.84 132.32 235.76 ;
      RECT 134.28 0.84 134.56 235.76 ;
      RECT 136.52 0.84 136.8 235.76 ;
      RECT 138.76 0.84 139.04 235.76 ;
      RECT 141 0.84 141.28 235.76 ;
      RECT 143.24 0.84 143.52 235.76 ;
      RECT 145.48 0.84 145.76 235.76 ;
      RECT 147.72 0.84 148 235.76 ;
      RECT 149.96 0.84 150.24 235.76 ;
      RECT 152.2 0.84 152.48 235.76 ;
      RECT 154.44 0.84 154.72 235.76 ;
      RECT 156.68 0.84 156.96 235.76 ;
      RECT 158.92 0.84 159.2 235.76 ;
      RECT 161.16 0.84 161.44 235.76 ;
      RECT 163.4 0.84 163.68 235.76 ;
      RECT 165.64 0.84 165.92 235.76 ;
      RECT 167.88 0.84 168.16 235.76 ;
      RECT 170.12 0.84 170.4 235.76 ;
      RECT 172.36 0.84 172.64 235.76 ;
      RECT 174.6 0.84 174.88 235.76 ;
      RECT 176.84 0.84 177.12 235.76 ;
      RECT 179.08 0.84 179.36 235.76 ;
      RECT 181.32 0.84 181.6 235.76 ;
      RECT 183.56 0.84 183.84 235.76 ;
      RECT 185.8 0.84 186.08 235.76 ;
      RECT 188.04 0.84 188.32 235.76 ;
      RECT 190.28 0.84 190.56 235.76 ;
      RECT 192.52 0.84 192.8 235.76 ;
      RECT 194.76 0.84 195.04 235.76 ;
      RECT 197 0.84 197.28 235.76 ;
      RECT 199.24 0.84 199.52 235.76 ;
      RECT 201.48 0.84 201.76 235.76 ;
      RECT 203.72 0.84 204 235.76 ;
      RECT 205.96 0.84 206.24 235.76 ;
      RECT 208.2 0.84 208.48 235.76 ;
      RECT 210.44 0.84 210.72 235.76 ;
      RECT 212.68 0.84 212.96 235.76 ;
      RECT 214.92 0.84 215.2 235.76 ;
      RECT 217.16 0.84 217.44 235.76 ;
      RECT 219.4 0.84 219.68 235.76 ;
      RECT 221.64 0.84 221.92 235.76 ;
      RECT 223.88 0.84 224.16 235.76 ;
      RECT 226.12 0.84 226.4 235.76 ;
      RECT 228.36 0.84 228.64 235.76 ;
      RECT 230.6 0.84 230.88 235.76 ;
      RECT 232.84 0.84 233.12 235.76 ;
      RECT 235.08 0.84 235.36 235.76 ;
      RECT 237.32 0.84 237.6 235.76 ;
    END
  END VDD
  OBS
    LAYER M1 ;
    RECT 0 0 237.88 236.6 ;
    LAYER M2 ;
    RECT 0 0 237.88 236.6 ;
  END
END ht45_rocketgemmini_rockettile_icache_data_arrays_0_ext_bottom

END LIBRARY
